VERSION 5.8 ;
BUSBITCHARS "[]" ;
DIVIDERCHAR "/" ;
UNITS
    DATABASE MICRONS 1000 ;
END UNITS

VIA ino_decode_queue_via1_2_1000_440_1_2_410_410
  VIARULE via1Array ;
  CUTSIZE 0.19 0.19 ;
  LAYERS Metal1 Via1 Metal2 ;
  CUTSPACING 0.22 0.22 ;
  ENCLOSURE 0.05 0.125 0.005 0.05 ;
  ROWCOL 1 2 ;
END ino_decode_queue_via1_2_1000_440_1_2_410_410

VIA ino_decode_queue_via2_3_1000_440_1_2_410_410
  VIARULE via2Array ;
  CUTSIZE 0.19 0.19 ;
  LAYERS Metal2 Via2 Metal3 ;
  CUTSPACING 0.22 0.22 ;
  ENCLOSURE 0.005 0.05 0.05 0.005 ;
  ROWCOL 1 2 ;
END ino_decode_queue_via2_3_1000_440_1_2_410_410

VIA ino_decode_queue_via3_4_1000_440_1_2_410_410
  VIARULE via3Array ;
  CUTSIZE 0.19 0.19 ;
  LAYERS Metal3 Via3 Metal4 ;
  CUTSPACING 0.22 0.22 ;
  ENCLOSURE 0.05 0.005 0.2 0.05 ;
  ROWCOL 1 2 ;
END ino_decode_queue_via3_4_1000_440_1_2_410_410

VIA ino_decode_queue_via4_5_1000_2000_1_1_840_840
  VIARULE viaTop1Array ;
  CUTSIZE 0.42 0.42 ;
  LAYERS Metal4 TopVia1 TopMetal1 ;
  CUTSPACING 0.42 0.42 ;
  ENCLOSURE 0.29 0.1 0.42 0.79 ;
END ino_decode_queue_via4_5_1000_2000_1_1_840_840

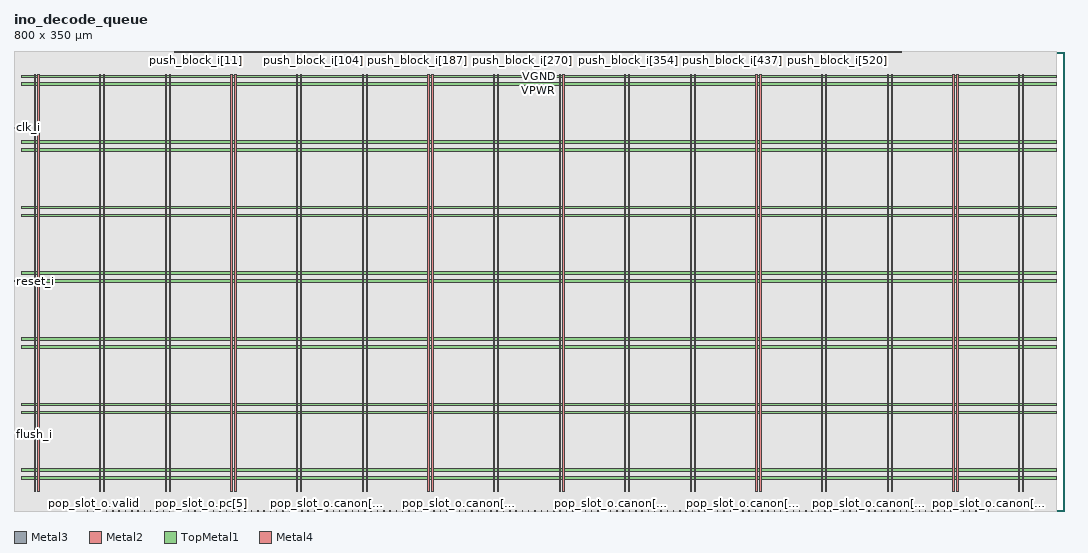
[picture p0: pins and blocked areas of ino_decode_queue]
MACRO ino_decode_queue
  FOREIGN ino_decode_queue 0 0 ;
  CLASS BLOCK ;
  SIZE 800 BY 350 ;
  PIN clk_i
    DIRECTION INPUT ;
    USE SIGNAL ;
    PORT
      LAYER Metal3 ;
        RECT  0 291.7 0.4 292.1 ;
    END
  END clk_i
  PIN flush_i
    DIRECTION INPUT ;
    USE SIGNAL ;
    PORT
      LAYER Metal3 ;
        RECT  0 58.18 0.4 58.58 ;
    END
  END flush_i
  PIN pop_slot_o.canon[0]
    DIRECTION OUTPUT ;
    USE SIGNAL ;
    PORT
      LAYER Metal2 ;
        RECT  65.56 0 65.96 0.4 ;
    END
  END pop_slot_o.canon[0]
  PIN pop_slot_o.canon[10]
    DIRECTION OUTPUT ;
    USE SIGNAL ;
    PORT
      LAYER Metal2 ;
        RECT  209.56 0 209.96 0.4 ;
    END
  END pop_slot_o.canon[10]
  PIN pop_slot_o.canon[11]
    DIRECTION OUTPUT ;
    USE SIGNAL ;
    PORT
      LAYER Metal2 ;
        RECT  223.96 0 224.36 0.4 ;
    END
  END pop_slot_o.canon[11]
  PIN pop_slot_o.canon[12]
    DIRECTION OUTPUT ;
    USE SIGNAL ;
    PORT
      LAYER Metal2 ;
        RECT  238.36 0 238.76 0.4 ;
    END
  END pop_slot_o.canon[12]
  PIN pop_slot_o.canon[13]
    DIRECTION OUTPUT ;
    USE SIGNAL ;
    PORT
      LAYER Metal2 ;
        RECT  252.76 0 253.16 0.4 ;
    END
  END pop_slot_o.canon[13]
  PIN pop_slot_o.canon[14]
    DIRECTION OUTPUT ;
    USE SIGNAL ;
    PORT
      LAYER Metal2 ;
        RECT  267.16 0 267.56 0.4 ;
    END
  END pop_slot_o.canon[14]
  PIN pop_slot_o.canon[15]
    DIRECTION OUTPUT ;
    USE SIGNAL ;
    PORT
      LAYER Metal2 ;
        RECT  281.56 0 281.96 0.4 ;
    END
  END pop_slot_o.canon[15]
  PIN pop_slot_o.canon[16]
    DIRECTION OUTPUT ;
    USE SIGNAL ;
    PORT
      LAYER Metal2 ;
        RECT  295.96 0 296.36 0.4 ;
    END
  END pop_slot_o.canon[16]
  PIN pop_slot_o.canon[17]
    DIRECTION OUTPUT ;
    USE SIGNAL ;
    PORT
      LAYER Metal2 ;
        RECT  310.36 0 310.76 0.4 ;
    END
  END pop_slot_o.canon[17]
  PIN pop_slot_o.canon[18]
    DIRECTION OUTPUT ;
    USE SIGNAL ;
    PORT
      LAYER Metal2 ;
        RECT  324.76 0 325.16 0.4 ;
    END
  END pop_slot_o.canon[18]
  PIN pop_slot_o.canon[19]
    DIRECTION OUTPUT ;
    USE SIGNAL ;
    PORT
      LAYER Metal2 ;
        RECT  339.16 0 339.56 0.4 ;
    END
  END pop_slot_o.canon[19]
  PIN pop_slot_o.canon[1]
    DIRECTION OUTPUT ;
    USE SIGNAL ;
    PORT
      LAYER Metal2 ;
        RECT  79.96 0 80.36 0.4 ;
    END
  END pop_slot_o.canon[1]
  PIN pop_slot_o.canon[20]
    DIRECTION OUTPUT ;
    USE SIGNAL ;
    PORT
      LAYER Metal2 ;
        RECT  353.56 0 353.96 0.4 ;
    END
  END pop_slot_o.canon[20]
  PIN pop_slot_o.canon[21]
    DIRECTION OUTPUT ;
    USE SIGNAL ;
    PORT
      LAYER Metal2 ;
        RECT  367.96 0 368.36 0.4 ;
    END
  END pop_slot_o.canon[21]
  PIN pop_slot_o.canon[22]
    DIRECTION OUTPUT ;
    USE SIGNAL ;
    PORT
      LAYER Metal2 ;
        RECT  382.36 0 382.76 0.4 ;
    END
  END pop_slot_o.canon[22]
  PIN pop_slot_o.canon[23]
    DIRECTION OUTPUT ;
    USE SIGNAL ;
    PORT
      LAYER Metal2 ;
        RECT  396.76 0 397.16 0.4 ;
    END
  END pop_slot_o.canon[23]
  PIN pop_slot_o.canon[24]
    DIRECTION OUTPUT ;
    USE SIGNAL ;
    PORT
      LAYER Metal2 ;
        RECT  411.16 0 411.56 0.4 ;
    END
  END pop_slot_o.canon[24]
  PIN pop_slot_o.canon[25]
    DIRECTION OUTPUT ;
    USE SIGNAL ;
    PORT
      LAYER Metal2 ;
        RECT  425.56 0 425.96 0.4 ;
    END
  END pop_slot_o.canon[25]
  PIN pop_slot_o.canon[26]
    DIRECTION OUTPUT ;
    USE SIGNAL ;
    PORT
      LAYER Metal2 ;
        RECT  439.96 0 440.36 0.4 ;
    END
  END pop_slot_o.canon[26]
  PIN pop_slot_o.canon[27]
    DIRECTION OUTPUT ;
    USE SIGNAL ;
    PORT
      LAYER Metal2 ;
        RECT  454.36 0 454.76 0.4 ;
    END
  END pop_slot_o.canon[27]
  PIN pop_slot_o.canon[28]
    DIRECTION OUTPUT ;
    USE SIGNAL ;
    PORT
      LAYER Metal2 ;
        RECT  468.76 0 469.16 0.4 ;
    END
  END pop_slot_o.canon[28]
  PIN pop_slot_o.canon[29]
    DIRECTION OUTPUT ;
    USE SIGNAL ;
    PORT
      LAYER Metal2 ;
        RECT  483.16 0 483.56 0.4 ;
    END
  END pop_slot_o.canon[29]
  PIN pop_slot_o.canon[2]
    DIRECTION OUTPUT ;
    USE SIGNAL ;
    PORT
      LAYER Metal2 ;
        RECT  94.36 0 94.76 0.4 ;
    END
  END pop_slot_o.canon[2]
  PIN pop_slot_o.canon[30]
    DIRECTION OUTPUT ;
    USE SIGNAL ;
    PORT
      LAYER Metal2 ;
        RECT  497.56 0 497.96 0.4 ;
    END
  END pop_slot_o.canon[30]
  PIN pop_slot_o.canon[31]
    DIRECTION OUTPUT ;
    USE SIGNAL ;
    PORT
      LAYER Metal2 ;
        RECT  511.96 0 512.36 0.4 ;
    END
  END pop_slot_o.canon[31]
  PIN pop_slot_o.canon[32]
    DIRECTION OUTPUT ;
    USE SIGNAL ;
    PORT
      LAYER Metal2 ;
        RECT  526.36 0 526.76 0.4 ;
    END
  END pop_slot_o.canon[32]
  PIN pop_slot_o.canon[33]
    DIRECTION OUTPUT ;
    USE SIGNAL ;
    PORT
      LAYER Metal2 ;
        RECT  535.96 0 536.36 0.4 ;
    END
  END pop_slot_o.canon[33]
  PIN pop_slot_o.canon[34]
    DIRECTION OUTPUT ;
    USE SIGNAL ;
    PORT
      LAYER Metal2 ;
        RECT  545.56 0 545.96 0.4 ;
    END
  END pop_slot_o.canon[34]
  PIN pop_slot_o.canon[35]
    DIRECTION OUTPUT ;
    USE SIGNAL ;
    PORT
      LAYER Metal2 ;
        RECT  555.16 0 555.56 0.4 ;
    END
  END pop_slot_o.canon[35]
  PIN pop_slot_o.canon[36]
    DIRECTION OUTPUT ;
    USE SIGNAL ;
    PORT
      LAYER Metal2 ;
        RECT  564.76 0 565.16 0.4 ;
    END
  END pop_slot_o.canon[36]
  PIN pop_slot_o.canon[37]
    DIRECTION OUTPUT ;
    USE SIGNAL ;
    PORT
      LAYER Metal2 ;
        RECT  574.36 0 574.76 0.4 ;
    END
  END pop_slot_o.canon[37]
  PIN pop_slot_o.canon[38]
    DIRECTION OUTPUT ;
    USE SIGNAL ;
    PORT
      LAYER Metal2 ;
        RECT  583.96 0 584.36 0.4 ;
    END
  END pop_slot_o.canon[38]
  PIN pop_slot_o.canon[39]
    DIRECTION OUTPUT ;
    USE SIGNAL ;
    PORT
      LAYER Metal2 ;
        RECT  593.56 0 593.96 0.4 ;
    END
  END pop_slot_o.canon[39]
  PIN pop_slot_o.canon[3]
    DIRECTION OUTPUT ;
    USE SIGNAL ;
    PORT
      LAYER Metal2 ;
        RECT  108.76 0 109.16 0.4 ;
    END
  END pop_slot_o.canon[3]
  PIN pop_slot_o.canon[40]
    DIRECTION OUTPUT ;
    USE SIGNAL ;
    PORT
      LAYER Metal2 ;
        RECT  603.16 0 603.56 0.4 ;
    END
  END pop_slot_o.canon[40]
  PIN pop_slot_o.canon[41]
    DIRECTION OUTPUT ;
    USE SIGNAL ;
    PORT
      LAYER Metal2 ;
        RECT  612.76 0 613.16 0.4 ;
    END
  END pop_slot_o.canon[41]
  PIN pop_slot_o.canon[42]
    DIRECTION OUTPUT ;
    USE SIGNAL ;
    PORT
      LAYER Metal2 ;
        RECT  622.36 0 622.76 0.4 ;
    END
  END pop_slot_o.canon[42]
  PIN pop_slot_o.canon[43]
    DIRECTION OUTPUT ;
    USE SIGNAL ;
    PORT
      LAYER Metal2 ;
        RECT  631.96 0 632.36 0.4 ;
    END
  END pop_slot_o.canon[43]
  PIN pop_slot_o.canon[44]
    DIRECTION OUTPUT ;
    USE SIGNAL ;
    PORT
      LAYER Metal2 ;
        RECT  641.56 0 641.96 0.4 ;
    END
  END pop_slot_o.canon[44]
  PIN pop_slot_o.canon[45]
    DIRECTION OUTPUT ;
    USE SIGNAL ;
    PORT
      LAYER Metal2 ;
        RECT  651.16 0 651.56 0.4 ;
    END
  END pop_slot_o.canon[45]
  PIN pop_slot_o.canon[46]
    DIRECTION OUTPUT ;
    USE SIGNAL ;
    PORT
      LAYER Metal2 ;
        RECT  660.76 0 661.16 0.4 ;
    END
  END pop_slot_o.canon[46]
  PIN pop_slot_o.canon[47]
    DIRECTION OUTPUT ;
    USE SIGNAL ;
    PORT
      LAYER Metal2 ;
        RECT  670.36 0 670.76 0.4 ;
    END
  END pop_slot_o.canon[47]
  PIN pop_slot_o.canon[48]
    DIRECTION OUTPUT ;
    USE SIGNAL ;
    PORT
      LAYER Metal2 ;
        RECT  679.96 0 680.36 0.4 ;
    END
  END pop_slot_o.canon[48]
  PIN pop_slot_o.canon[49]
    DIRECTION OUTPUT ;
    USE SIGNAL ;
    PORT
      LAYER Metal2 ;
        RECT  689.56 0 689.96 0.4 ;
    END
  END pop_slot_o.canon[49]
  PIN pop_slot_o.canon[4]
    DIRECTION OUTPUT ;
    USE SIGNAL ;
    PORT
      LAYER Metal2 ;
        RECT  123.16 0 123.56 0.4 ;
    END
  END pop_slot_o.canon[4]
  PIN pop_slot_o.canon[50]
    DIRECTION OUTPUT ;
    USE SIGNAL ;
    PORT
      LAYER Metal2 ;
        RECT  699.16 0 699.56 0.4 ;
    END
  END pop_slot_o.canon[50]
  PIN pop_slot_o.canon[51]
    DIRECTION OUTPUT ;
    USE SIGNAL ;
    PORT
      LAYER Metal2 ;
        RECT  708.76 0 709.16 0.4 ;
    END
  END pop_slot_o.canon[51]
  PIN pop_slot_o.canon[52]
    DIRECTION OUTPUT ;
    USE SIGNAL ;
    PORT
      LAYER Metal2 ;
        RECT  718.36 0 718.76 0.4 ;
    END
  END pop_slot_o.canon[52]
  PIN pop_slot_o.canon[53]
    DIRECTION OUTPUT ;
    USE SIGNAL ;
    PORT
      LAYER Metal2 ;
        RECT  727.96 0 728.36 0.4 ;
    END
  END pop_slot_o.canon[53]
  PIN pop_slot_o.canon[54]
    DIRECTION OUTPUT ;
    USE SIGNAL ;
    PORT
      LAYER Metal2 ;
        RECT  737.56 0 737.96 0.4 ;
    END
  END pop_slot_o.canon[54]
  PIN pop_slot_o.canon[55]
    DIRECTION OUTPUT ;
    USE SIGNAL ;
    PORT
      LAYER Metal2 ;
        RECT  742.36 0 742.76 0.4 ;
    END
  END pop_slot_o.canon[55]
  PIN pop_slot_o.canon[5]
    DIRECTION OUTPUT ;
    USE SIGNAL ;
    PORT
      LAYER Metal2 ;
        RECT  137.56 0 137.96 0.4 ;
    END
  END pop_slot_o.canon[5]
  PIN pop_slot_o.canon[6]
    DIRECTION OUTPUT ;
    USE SIGNAL ;
    PORT
      LAYER Metal2 ;
        RECT  151.96 0 152.36 0.4 ;
    END
  END pop_slot_o.canon[6]
  PIN pop_slot_o.canon[7]
    DIRECTION OUTPUT ;
    USE SIGNAL ;
    PORT
      LAYER Metal2 ;
        RECT  166.36 0 166.76 0.4 ;
    END
  END pop_slot_o.canon[7]
  PIN pop_slot_o.canon[8]
    DIRECTION OUTPUT ;
    USE SIGNAL ;
    PORT
      LAYER Metal2 ;
        RECT  180.76 0 181.16 0.4 ;
    END
  END pop_slot_o.canon[8]
  PIN pop_slot_o.canon[9]
    DIRECTION OUTPUT ;
    USE SIGNAL ;
    PORT
      LAYER Metal2 ;
        RECT  195.16 0 195.56 0.4 ;
    END
  END pop_slot_o.canon[9]
  PIN pop_slot_o.pc[0]
    DIRECTION OUTPUT ;
    USE SIGNAL ;
    PORT
      LAYER Metal2 ;
        RECT  70.36 0 70.76 0.4 ;
    END
  END pop_slot_o.pc[0]
  PIN pop_slot_o.pc[10]
    DIRECTION OUTPUT ;
    USE SIGNAL ;
    PORT
      LAYER Metal2 ;
        RECT  214.36 0 214.76 0.4 ;
    END
  END pop_slot_o.pc[10]
  PIN pop_slot_o.pc[11]
    DIRECTION OUTPUT ;
    USE SIGNAL ;
    PORT
      LAYER Metal2 ;
        RECT  228.76 0 229.16 0.4 ;
    END
  END pop_slot_o.pc[11]
  PIN pop_slot_o.pc[12]
    DIRECTION OUTPUT ;
    USE SIGNAL ;
    PORT
      LAYER Metal2 ;
        RECT  243.16 0 243.56 0.4 ;
    END
  END pop_slot_o.pc[12]
  PIN pop_slot_o.pc[13]
    DIRECTION OUTPUT ;
    USE SIGNAL ;
    PORT
      LAYER Metal2 ;
        RECT  257.56 0 257.96 0.4 ;
    END
  END pop_slot_o.pc[13]
  PIN pop_slot_o.pc[14]
    DIRECTION OUTPUT ;
    USE SIGNAL ;
    PORT
      LAYER Metal2 ;
        RECT  271.96 0 272.36 0.4 ;
    END
  END pop_slot_o.pc[14]
  PIN pop_slot_o.pc[15]
    DIRECTION OUTPUT ;
    USE SIGNAL ;
    PORT
      LAYER Metal2 ;
        RECT  286.36 0 286.76 0.4 ;
    END
  END pop_slot_o.pc[15]
  PIN pop_slot_o.pc[16]
    DIRECTION OUTPUT ;
    USE SIGNAL ;
    PORT
      LAYER Metal2 ;
        RECT  300.76 0 301.16 0.4 ;
    END
  END pop_slot_o.pc[16]
  PIN pop_slot_o.pc[17]
    DIRECTION OUTPUT ;
    USE SIGNAL ;
    PORT
      LAYER Metal2 ;
        RECT  315.16 0 315.56 0.4 ;
    END
  END pop_slot_o.pc[17]
  PIN pop_slot_o.pc[18]
    DIRECTION OUTPUT ;
    USE SIGNAL ;
    PORT
      LAYER Metal2 ;
        RECT  329.56 0 329.96 0.4 ;
    END
  END pop_slot_o.pc[18]
  PIN pop_slot_o.pc[19]
    DIRECTION OUTPUT ;
    USE SIGNAL ;
    PORT
      LAYER Metal2 ;
        RECT  343.96 0 344.36 0.4 ;
    END
  END pop_slot_o.pc[19]
  PIN pop_slot_o.pc[1]
    DIRECTION OUTPUT ;
    USE SIGNAL ;
    PORT
      LAYER Metal2 ;
        RECT  84.76 0 85.16 0.4 ;
    END
  END pop_slot_o.pc[1]
  PIN pop_slot_o.pc[20]
    DIRECTION OUTPUT ;
    USE SIGNAL ;
    PORT
      LAYER Metal2 ;
        RECT  358.36 0 358.76 0.4 ;
    END
  END pop_slot_o.pc[20]
  PIN pop_slot_o.pc[21]
    DIRECTION OUTPUT ;
    USE SIGNAL ;
    PORT
      LAYER Metal2 ;
        RECT  372.76 0 373.16 0.4 ;
    END
  END pop_slot_o.pc[21]
  PIN pop_slot_o.pc[22]
    DIRECTION OUTPUT ;
    USE SIGNAL ;
    PORT
      LAYER Metal2 ;
        RECT  387.16 0 387.56 0.4 ;
    END
  END pop_slot_o.pc[22]
  PIN pop_slot_o.pc[23]
    DIRECTION OUTPUT ;
    USE SIGNAL ;
    PORT
      LAYER Metal2 ;
        RECT  401.56 0 401.96 0.4 ;
    END
  END pop_slot_o.pc[23]
  PIN pop_slot_o.pc[24]
    DIRECTION OUTPUT ;
    USE SIGNAL ;
    PORT
      LAYER Metal2 ;
        RECT  415.96 0 416.36 0.4 ;
    END
  END pop_slot_o.pc[24]
  PIN pop_slot_o.pc[25]
    DIRECTION OUTPUT ;
    USE SIGNAL ;
    PORT
      LAYER Metal2 ;
        RECT  430.36 0 430.76 0.4 ;
    END
  END pop_slot_o.pc[25]
  PIN pop_slot_o.pc[26]
    DIRECTION OUTPUT ;
    USE SIGNAL ;
    PORT
      LAYER Metal2 ;
        RECT  444.76 0 445.16 0.4 ;
    END
  END pop_slot_o.pc[26]
  PIN pop_slot_o.pc[27]
    DIRECTION OUTPUT ;
    USE SIGNAL ;
    PORT
      LAYER Metal2 ;
        RECT  459.16 0 459.56 0.4 ;
    END
  END pop_slot_o.pc[27]
  PIN pop_slot_o.pc[28]
    DIRECTION OUTPUT ;
    USE SIGNAL ;
    PORT
      LAYER Metal2 ;
        RECT  473.56 0 473.96 0.4 ;
    END
  END pop_slot_o.pc[28]
  PIN pop_slot_o.pc[29]
    DIRECTION OUTPUT ;
    USE SIGNAL ;
    PORT
      LAYER Metal2 ;
        RECT  487.96 0 488.36 0.4 ;
    END
  END pop_slot_o.pc[29]
  PIN pop_slot_o.pc[2]
    DIRECTION OUTPUT ;
    USE SIGNAL ;
    PORT
      LAYER Metal2 ;
        RECT  99.16 0 99.56 0.4 ;
    END
  END pop_slot_o.pc[2]
  PIN pop_slot_o.pc[30]
    DIRECTION OUTPUT ;
    USE SIGNAL ;
    PORT
      LAYER Metal2 ;
        RECT  502.36 0 502.76 0.4 ;
    END
  END pop_slot_o.pc[30]
  PIN pop_slot_o.pc[31]
    DIRECTION OUTPUT ;
    USE SIGNAL ;
    PORT
      LAYER Metal2 ;
        RECT  516.76 0 517.16 0.4 ;
    END
  END pop_slot_o.pc[31]
  PIN pop_slot_o.pc[3]
    DIRECTION OUTPUT ;
    USE SIGNAL ;
    PORT
      LAYER Metal2 ;
        RECT  113.56 0 113.96 0.4 ;
    END
  END pop_slot_o.pc[3]
  PIN pop_slot_o.pc[4]
    DIRECTION OUTPUT ;
    USE SIGNAL ;
    PORT
      LAYER Metal2 ;
        RECT  127.96 0 128.36 0.4 ;
    END
  END pop_slot_o.pc[4]
  PIN pop_slot_o.pc[5]
    DIRECTION OUTPUT ;
    USE SIGNAL ;
    PORT
      LAYER Metal2 ;
        RECT  142.36 0 142.76 0.4 ;
    END
  END pop_slot_o.pc[5]
  PIN pop_slot_o.pc[6]
    DIRECTION OUTPUT ;
    USE SIGNAL ;
    PORT
      LAYER Metal2 ;
        RECT  156.76 0 157.16 0.4 ;
    END
  END pop_slot_o.pc[6]
  PIN pop_slot_o.pc[7]
    DIRECTION OUTPUT ;
    USE SIGNAL ;
    PORT
      LAYER Metal2 ;
        RECT  171.16 0 171.56 0.4 ;
    END
  END pop_slot_o.pc[7]
  PIN pop_slot_o.pc[8]
    DIRECTION OUTPUT ;
    USE SIGNAL ;
    PORT
      LAYER Metal2 ;
        RECT  185.56 0 185.96 0.4 ;
    END
  END pop_slot_o.pc[8]
  PIN pop_slot_o.pc[9]
    DIRECTION OUTPUT ;
    USE SIGNAL ;
    PORT
      LAYER Metal2 ;
        RECT  199.96 0 200.36 0.4 ;
    END
  END pop_slot_o.pc[9]
  PIN pop_slot_o.pred[0]
    DIRECTION OUTPUT ;
    USE SIGNAL ;
    PORT
      LAYER Metal2 ;
        RECT  75.16 0 75.56 0.4 ;
    END
  END pop_slot_o.pred[0]
  PIN pop_slot_o.pred[10]
    DIRECTION OUTPUT ;
    USE SIGNAL ;
    PORT
      LAYER Metal2 ;
        RECT  219.16 0 219.56 0.4 ;
    END
  END pop_slot_o.pred[10]
  PIN pop_slot_o.pred[11]
    DIRECTION OUTPUT ;
    USE SIGNAL ;
    PORT
      LAYER Metal2 ;
        RECT  233.56 0 233.96 0.4 ;
    END
  END pop_slot_o.pred[11]
  PIN pop_slot_o.pred[12]
    DIRECTION OUTPUT ;
    USE SIGNAL ;
    PORT
      LAYER Metal2 ;
        RECT  247.96 0 248.36 0.4 ;
    END
  END pop_slot_o.pred[12]
  PIN pop_slot_o.pred[13]
    DIRECTION OUTPUT ;
    USE SIGNAL ;
    PORT
      LAYER Metal2 ;
        RECT  262.36 0 262.76 0.4 ;
    END
  END pop_slot_o.pred[13]
  PIN pop_slot_o.pred[14]
    DIRECTION OUTPUT ;
    USE SIGNAL ;
    PORT
      LAYER Metal2 ;
        RECT  276.76 0 277.16 0.4 ;
    END
  END pop_slot_o.pred[14]
  PIN pop_slot_o.pred[15]
    DIRECTION OUTPUT ;
    USE SIGNAL ;
    PORT
      LAYER Metal2 ;
        RECT  291.16 0 291.56 0.4 ;
    END
  END pop_slot_o.pred[15]
  PIN pop_slot_o.pred[16]
    DIRECTION OUTPUT ;
    USE SIGNAL ;
    PORT
      LAYER Metal2 ;
        RECT  305.56 0 305.96 0.4 ;
    END
  END pop_slot_o.pred[16]
  PIN pop_slot_o.pred[17]
    DIRECTION OUTPUT ;
    USE SIGNAL ;
    PORT
      LAYER Metal2 ;
        RECT  319.96 0 320.36 0.4 ;
    END
  END pop_slot_o.pred[17]
  PIN pop_slot_o.pred[18]
    DIRECTION OUTPUT ;
    USE SIGNAL ;
    PORT
      LAYER Metal2 ;
        RECT  334.36 0 334.76 0.4 ;
    END
  END pop_slot_o.pred[18]
  PIN pop_slot_o.pred[19]
    DIRECTION OUTPUT ;
    USE SIGNAL ;
    PORT
      LAYER Metal2 ;
        RECT  348.76 0 349.16 0.4 ;
    END
  END pop_slot_o.pred[19]
  PIN pop_slot_o.pred[1]
    DIRECTION OUTPUT ;
    USE SIGNAL ;
    PORT
      LAYER Metal2 ;
        RECT  89.56 0 89.96 0.4 ;
    END
  END pop_slot_o.pred[1]
  PIN pop_slot_o.pred[20]
    DIRECTION OUTPUT ;
    USE SIGNAL ;
    PORT
      LAYER Metal2 ;
        RECT  363.16 0 363.56 0.4 ;
    END
  END pop_slot_o.pred[20]
  PIN pop_slot_o.pred[21]
    DIRECTION OUTPUT ;
    USE SIGNAL ;
    PORT
      LAYER Metal2 ;
        RECT  377.56 0 377.96 0.4 ;
    END
  END pop_slot_o.pred[21]
  PIN pop_slot_o.pred[22]
    DIRECTION OUTPUT ;
    USE SIGNAL ;
    PORT
      LAYER Metal2 ;
        RECT  391.96 0 392.36 0.4 ;
    END
  END pop_slot_o.pred[22]
  PIN pop_slot_o.pred[23]
    DIRECTION OUTPUT ;
    USE SIGNAL ;
    PORT
      LAYER Metal2 ;
        RECT  406.36 0 406.76 0.4 ;
    END
  END pop_slot_o.pred[23]
  PIN pop_slot_o.pred[24]
    DIRECTION OUTPUT ;
    USE SIGNAL ;
    PORT
      LAYER Metal2 ;
        RECT  420.76 0 421.16 0.4 ;
    END
  END pop_slot_o.pred[24]
  PIN pop_slot_o.pred[25]
    DIRECTION OUTPUT ;
    USE SIGNAL ;
    PORT
      LAYER Metal2 ;
        RECT  435.16 0 435.56 0.4 ;
    END
  END pop_slot_o.pred[25]
  PIN pop_slot_o.pred[26]
    DIRECTION OUTPUT ;
    USE SIGNAL ;
    PORT
      LAYER Metal2 ;
        RECT  449.56 0 449.96 0.4 ;
    END
  END pop_slot_o.pred[26]
  PIN pop_slot_o.pred[27]
    DIRECTION OUTPUT ;
    USE SIGNAL ;
    PORT
      LAYER Metal2 ;
        RECT  463.96 0 464.36 0.4 ;
    END
  END pop_slot_o.pred[27]
  PIN pop_slot_o.pred[28]
    DIRECTION OUTPUT ;
    USE SIGNAL ;
    PORT
      LAYER Metal2 ;
        RECT  478.36 0 478.76 0.4 ;
    END
  END pop_slot_o.pred[28]
  PIN pop_slot_o.pred[29]
    DIRECTION OUTPUT ;
    USE SIGNAL ;
    PORT
      LAYER Metal2 ;
        RECT  492.76 0 493.16 0.4 ;
    END
  END pop_slot_o.pred[29]
  PIN pop_slot_o.pred[2]
    DIRECTION OUTPUT ;
    USE SIGNAL ;
    PORT
      LAYER Metal2 ;
        RECT  103.96 0 104.36 0.4 ;
    END
  END pop_slot_o.pred[2]
  PIN pop_slot_o.pred[30]
    DIRECTION OUTPUT ;
    USE SIGNAL ;
    PORT
      LAYER Metal2 ;
        RECT  507.16 0 507.56 0.4 ;
    END
  END pop_slot_o.pred[30]
  PIN pop_slot_o.pred[31]
    DIRECTION OUTPUT ;
    USE SIGNAL ;
    PORT
      LAYER Metal2 ;
        RECT  521.56 0 521.96 0.4 ;
    END
  END pop_slot_o.pred[31]
  PIN pop_slot_o.pred[32]
    DIRECTION OUTPUT ;
    USE SIGNAL ;
    PORT
      LAYER Metal2 ;
        RECT  531.16 0 531.56 0.4 ;
    END
  END pop_slot_o.pred[32]
  PIN pop_slot_o.pred[33]
    DIRECTION OUTPUT ;
    USE SIGNAL ;
    PORT
      LAYER Metal2 ;
        RECT  540.76 0 541.16 0.4 ;
    END
  END pop_slot_o.pred[33]
  PIN pop_slot_o.pred[34]
    DIRECTION OUTPUT ;
    USE SIGNAL ;
    PORT
      LAYER Metal2 ;
        RECT  550.36 0 550.76 0.4 ;
    END
  END pop_slot_o.pred[34]
  PIN pop_slot_o.pred[35]
    DIRECTION OUTPUT ;
    USE SIGNAL ;
    PORT
      LAYER Metal2 ;
        RECT  559.96 0 560.36 0.4 ;
    END
  END pop_slot_o.pred[35]
  PIN pop_slot_o.pred[36]
    DIRECTION OUTPUT ;
    USE SIGNAL ;
    PORT
      LAYER Metal2 ;
        RECT  569.56 0 569.96 0.4 ;
    END
  END pop_slot_o.pred[36]
  PIN pop_slot_o.pred[37]
    DIRECTION OUTPUT ;
    USE SIGNAL ;
    PORT
      LAYER Metal2 ;
        RECT  579.16 0 579.56 0.4 ;
    END
  END pop_slot_o.pred[37]
  PIN pop_slot_o.pred[38]
    DIRECTION OUTPUT ;
    USE SIGNAL ;
    PORT
      LAYER Metal2 ;
        RECT  588.76 0 589.16 0.4 ;
    END
  END pop_slot_o.pred[38]
  PIN pop_slot_o.pred[39]
    DIRECTION OUTPUT ;
    USE SIGNAL ;
    PORT
      LAYER Metal2 ;
        RECT  598.36 0 598.76 0.4 ;
    END
  END pop_slot_o.pred[39]
  PIN pop_slot_o.pred[3]
    DIRECTION OUTPUT ;
    USE SIGNAL ;
    PORT
      LAYER Metal2 ;
        RECT  118.36 0 118.76 0.4 ;
    END
  END pop_slot_o.pred[3]
  PIN pop_slot_o.pred[40]
    DIRECTION OUTPUT ;
    USE SIGNAL ;
    PORT
      LAYER Metal2 ;
        RECT  607.96 0 608.36 0.4 ;
    END
  END pop_slot_o.pred[40]
  PIN pop_slot_o.pred[41]
    DIRECTION OUTPUT ;
    USE SIGNAL ;
    PORT
      LAYER Metal2 ;
        RECT  617.56 0 617.96 0.4 ;
    END
  END pop_slot_o.pred[41]
  PIN pop_slot_o.pred[42]
    DIRECTION OUTPUT ;
    USE SIGNAL ;
    PORT
      LAYER Metal2 ;
        RECT  627.16 0 627.56 0.4 ;
    END
  END pop_slot_o.pred[42]
  PIN pop_slot_o.pred[43]
    DIRECTION OUTPUT ;
    USE SIGNAL ;
    PORT
      LAYER Metal2 ;
        RECT  636.76 0 637.16 0.4 ;
    END
  END pop_slot_o.pred[43]
  PIN pop_slot_o.pred[44]
    DIRECTION OUTPUT ;
    USE SIGNAL ;
    PORT
      LAYER Metal2 ;
        RECT  646.36 0 646.76 0.4 ;
    END
  END pop_slot_o.pred[44]
  PIN pop_slot_o.pred[45]
    DIRECTION OUTPUT ;
    USE SIGNAL ;
    PORT
      LAYER Metal2 ;
        RECT  655.96 0 656.36 0.4 ;
    END
  END pop_slot_o.pred[45]
  PIN pop_slot_o.pred[46]
    DIRECTION OUTPUT ;
    USE SIGNAL ;
    PORT
      LAYER Metal2 ;
        RECT  665.56 0 665.96 0.4 ;
    END
  END pop_slot_o.pred[46]
  PIN pop_slot_o.pred[47]
    DIRECTION OUTPUT ;
    USE SIGNAL ;
    PORT
      LAYER Metal2 ;
        RECT  675.16 0 675.56 0.4 ;
    END
  END pop_slot_o.pred[47]
  PIN pop_slot_o.pred[48]
    DIRECTION OUTPUT ;
    USE SIGNAL ;
    PORT
      LAYER Metal2 ;
        RECT  684.76 0 685.16 0.4 ;
    END
  END pop_slot_o.pred[48]
  PIN pop_slot_o.pred[49]
    DIRECTION OUTPUT ;
    USE SIGNAL ;
    PORT
      LAYER Metal2 ;
        RECT  694.36 0 694.76 0.4 ;
    END
  END pop_slot_o.pred[49]
  PIN pop_slot_o.pred[4]
    DIRECTION OUTPUT ;
    USE SIGNAL ;
    PORT
      LAYER Metal2 ;
        RECT  132.76 0 133.16 0.4 ;
    END
  END pop_slot_o.pred[4]
  PIN pop_slot_o.pred[50]
    DIRECTION OUTPUT ;
    USE SIGNAL ;
    PORT
      LAYER Metal2 ;
        RECT  703.96 0 704.36 0.4 ;
    END
  END pop_slot_o.pred[50]
  PIN pop_slot_o.pred[51]
    DIRECTION OUTPUT ;
    USE SIGNAL ;
    PORT
      LAYER Metal2 ;
        RECT  713.56 0 713.96 0.4 ;
    END
  END pop_slot_o.pred[51]
  PIN pop_slot_o.pred[52]
    DIRECTION OUTPUT ;
    USE SIGNAL ;
    PORT
      LAYER Metal2 ;
        RECT  723.16 0 723.56 0.4 ;
    END
  END pop_slot_o.pred[52]
  PIN pop_slot_o.pred[53]
    DIRECTION OUTPUT ;
    USE SIGNAL ;
    PORT
      LAYER Metal2 ;
        RECT  732.76 0 733.16 0.4 ;
    END
  END pop_slot_o.pred[53]
  PIN pop_slot_o.pred[5]
    DIRECTION OUTPUT ;
    USE SIGNAL ;
    PORT
      LAYER Metal2 ;
        RECT  147.16 0 147.56 0.4 ;
    END
  END pop_slot_o.pred[5]
  PIN pop_slot_o.pred[6]
    DIRECTION OUTPUT ;
    USE SIGNAL ;
    PORT
      LAYER Metal2 ;
        RECT  161.56 0 161.96 0.4 ;
    END
  END pop_slot_o.pred[6]
  PIN pop_slot_o.pred[7]
    DIRECTION OUTPUT ;
    USE SIGNAL ;
    PORT
      LAYER Metal2 ;
        RECT  175.96 0 176.36 0.4 ;
    END
  END pop_slot_o.pred[7]
  PIN pop_slot_o.pred[8]
    DIRECTION OUTPUT ;
    USE SIGNAL ;
    PORT
      LAYER Metal2 ;
        RECT  190.36 0 190.76 0.4 ;
    END
  END pop_slot_o.pred[8]
  PIN pop_slot_o.pred[9]
    DIRECTION OUTPUT ;
    USE SIGNAL ;
    PORT
      LAYER Metal2 ;
        RECT  204.76 0 205.16 0.4 ;
    END
  END pop_slot_o.pred[9]
  PIN pop_slot_o.valid
    DIRECTION OUTPUT ;
    USE SIGNAL ;
    PORT
      LAYER Metal2 ;
        RECT  60.76 0 61.16 0.4 ;
    END
  END pop_slot_o.valid
  PIN pop_take_i
    DIRECTION INPUT ;
    USE SIGNAL ;
    PORT
      LAYER Metal2 ;
        RECT  55.96 0 56.36 0.4 ;
    END
  END pop_take_i
  PIN push_block_i[0]
    DIRECTION INPUT ;
    USE SIGNAL ;
    PORT
      LAYER Metal2 ;
        RECT  127.96 349.6 128.36 350 ;
    END
  END push_block_i[0]
  PIN push_block_i[100]
    DIRECTION INPUT ;
    USE SIGNAL ;
    PORT
      LAYER Metal2 ;
        RECT  223.96 349.6 224.36 350 ;
    END
  END push_block_i[100]
  PIN push_block_i[101]
    DIRECTION INPUT ;
    USE SIGNAL ;
    PORT
      LAYER Metal2 ;
        RECT  224.92 349.6 225.32 350 ;
    END
  END push_block_i[101]
  PIN push_block_i[102]
    DIRECTION INPUT ;
    USE SIGNAL ;
    PORT
      LAYER Metal2 ;
        RECT  225.88 349.6 226.28 350 ;
    END
  END push_block_i[102]
  PIN push_block_i[103]
    DIRECTION INPUT ;
    USE SIGNAL ;
    PORT
      LAYER Metal2 ;
        RECT  226.84 349.6 227.24 350 ;
    END
  END push_block_i[103]
  PIN push_block_i[104]
    DIRECTION INPUT ;
    USE SIGNAL ;
    PORT
      LAYER Metal2 ;
        RECT  227.8 349.6 228.2 350 ;
    END
  END push_block_i[104]
  PIN push_block_i[105]
    DIRECTION INPUT ;
    USE SIGNAL ;
    PORT
      LAYER Metal2 ;
        RECT  228.76 349.6 229.16 350 ;
    END
  END push_block_i[105]
  PIN push_block_i[106]
    DIRECTION INPUT ;
    USE SIGNAL ;
    PORT
      LAYER Metal2 ;
        RECT  229.72 349.6 230.12 350 ;
    END
  END push_block_i[106]
  PIN push_block_i[107]
    DIRECTION INPUT ;
    USE SIGNAL ;
    PORT
      LAYER Metal2 ;
        RECT  230.68 349.6 231.08 350 ;
    END
  END push_block_i[107]
  PIN push_block_i[108]
    DIRECTION INPUT ;
    USE SIGNAL ;
    PORT
      LAYER Metal2 ;
        RECT  231.64 349.6 232.04 350 ;
    END
  END push_block_i[108]
  PIN push_block_i[109]
    DIRECTION INPUT ;
    USE SIGNAL ;
    PORT
      LAYER Metal2 ;
        RECT  232.6 349.6 233 350 ;
    END
  END push_block_i[109]
  PIN push_block_i[10]
    DIRECTION INPUT ;
    USE SIGNAL ;
    PORT
      LAYER Metal2 ;
        RECT  137.56 349.6 137.96 350 ;
    END
  END push_block_i[10]
  PIN push_block_i[110]
    DIRECTION INPUT ;
    USE SIGNAL ;
    PORT
      LAYER Metal2 ;
        RECT  233.56 349.6 233.96 350 ;
    END
  END push_block_i[110]
  PIN push_block_i[111]
    DIRECTION INPUT ;
    USE SIGNAL ;
    PORT
      LAYER Metal2 ;
        RECT  234.52 349.6 234.92 350 ;
    END
  END push_block_i[111]
  PIN push_block_i[112]
    DIRECTION INPUT ;
    USE SIGNAL ;
    PORT
      LAYER Metal2 ;
        RECT  235.48 349.6 235.88 350 ;
    END
  END push_block_i[112]
  PIN push_block_i[113]
    DIRECTION INPUT ;
    USE SIGNAL ;
    PORT
      LAYER Metal2 ;
        RECT  236.44 349.6 236.84 350 ;
    END
  END push_block_i[113]
  PIN push_block_i[114]
    DIRECTION INPUT ;
    USE SIGNAL ;
    PORT
      LAYER Metal2 ;
        RECT  237.4 349.6 237.8 350 ;
    END
  END push_block_i[114]
  PIN push_block_i[115]
    DIRECTION INPUT ;
    USE SIGNAL ;
    PORT
      LAYER Metal2 ;
        RECT  238.36 349.6 238.76 350 ;
    END
  END push_block_i[115]
  PIN push_block_i[116]
    DIRECTION INPUT ;
    USE SIGNAL ;
    PORT
      LAYER Metal2 ;
        RECT  239.32 349.6 239.72 350 ;
    END
  END push_block_i[116]
  PIN push_block_i[117]
    DIRECTION INPUT ;
    USE SIGNAL ;
    PORT
      LAYER Metal2 ;
        RECT  240.28 349.6 240.68 350 ;
    END
  END push_block_i[117]
  PIN push_block_i[118]
    DIRECTION INPUT ;
    USE SIGNAL ;
    PORT
      LAYER Metal2 ;
        RECT  241.24 349.6 241.64 350 ;
    END
  END push_block_i[118]
  PIN push_block_i[119]
    DIRECTION INPUT ;
    USE SIGNAL ;
    PORT
      LAYER Metal2 ;
        RECT  242.2 349.6 242.6 350 ;
    END
  END push_block_i[119]
  PIN push_block_i[11]
    DIRECTION INPUT ;
    USE SIGNAL ;
    PORT
      LAYER Metal2 ;
        RECT  138.52 349.6 138.92 350 ;
    END
  END push_block_i[11]
  PIN push_block_i[120]
    DIRECTION INPUT ;
    USE SIGNAL ;
    PORT
      LAYER Metal2 ;
        RECT  243.16 349.6 243.56 350 ;
    END
  END push_block_i[120]
  PIN push_block_i[121]
    DIRECTION INPUT ;
    USE SIGNAL ;
    PORT
      LAYER Metal2 ;
        RECT  244.12 349.6 244.52 350 ;
    END
  END push_block_i[121]
  PIN push_block_i[122]
    DIRECTION INPUT ;
    USE SIGNAL ;
    PORT
      LAYER Metal2 ;
        RECT  245.08 349.6 245.48 350 ;
    END
  END push_block_i[122]
  PIN push_block_i[123]
    DIRECTION INPUT ;
    USE SIGNAL ;
    PORT
      LAYER Metal2 ;
        RECT  246.04 349.6 246.44 350 ;
    END
  END push_block_i[123]
  PIN push_block_i[124]
    DIRECTION INPUT ;
    USE SIGNAL ;
    PORT
      LAYER Metal2 ;
        RECT  247 349.6 247.4 350 ;
    END
  END push_block_i[124]
  PIN push_block_i[125]
    DIRECTION INPUT ;
    USE SIGNAL ;
    PORT
      LAYER Metal2 ;
        RECT  247.96 349.6 248.36 350 ;
    END
  END push_block_i[125]
  PIN push_block_i[126]
    DIRECTION INPUT ;
    USE SIGNAL ;
    PORT
      LAYER Metal2 ;
        RECT  248.92 349.6 249.32 350 ;
    END
  END push_block_i[126]
  PIN push_block_i[127]
    DIRECTION INPUT ;
    USE SIGNAL ;
    PORT
      LAYER Metal2 ;
        RECT  249.88 349.6 250.28 350 ;
    END
  END push_block_i[127]
  PIN push_block_i[128]
    DIRECTION INPUT ;
    USE SIGNAL ;
    PORT
      LAYER Metal2 ;
        RECT  250.84 349.6 251.24 350 ;
    END
  END push_block_i[128]
  PIN push_block_i[129]
    DIRECTION INPUT ;
    USE SIGNAL ;
    PORT
      LAYER Metal2 ;
        RECT  251.8 349.6 252.2 350 ;
    END
  END push_block_i[129]
  PIN push_block_i[12]
    DIRECTION INPUT ;
    USE SIGNAL ;
    PORT
      LAYER Metal2 ;
        RECT  139.48 349.6 139.88 350 ;
    END
  END push_block_i[12]
  PIN push_block_i[130]
    DIRECTION INPUT ;
    USE SIGNAL ;
    PORT
      LAYER Metal2 ;
        RECT  252.76 349.6 253.16 350 ;
    END
  END push_block_i[130]
  PIN push_block_i[131]
    DIRECTION INPUT ;
    USE SIGNAL ;
    PORT
      LAYER Metal2 ;
        RECT  253.72 349.6 254.12 350 ;
    END
  END push_block_i[131]
  PIN push_block_i[132]
    DIRECTION INPUT ;
    USE SIGNAL ;
    PORT
      LAYER Metal2 ;
        RECT  254.68 349.6 255.08 350 ;
    END
  END push_block_i[132]
  PIN push_block_i[133]
    DIRECTION INPUT ;
    USE SIGNAL ;
    PORT
      LAYER Metal2 ;
        RECT  255.64 349.6 256.04 350 ;
    END
  END push_block_i[133]
  PIN push_block_i[134]
    DIRECTION INPUT ;
    USE SIGNAL ;
    PORT
      LAYER Metal2 ;
        RECT  256.6 349.6 257 350 ;
    END
  END push_block_i[134]
  PIN push_block_i[135]
    DIRECTION INPUT ;
    USE SIGNAL ;
    PORT
      LAYER Metal2 ;
        RECT  257.56 349.6 257.96 350 ;
    END
  END push_block_i[135]
  PIN push_block_i[136]
    DIRECTION INPUT ;
    USE SIGNAL ;
    PORT
      LAYER Metal2 ;
        RECT  258.52 349.6 258.92 350 ;
    END
  END push_block_i[136]
  PIN push_block_i[137]
    DIRECTION INPUT ;
    USE SIGNAL ;
    PORT
      LAYER Metal2 ;
        RECT  259.48 349.6 259.88 350 ;
    END
  END push_block_i[137]
  PIN push_block_i[138]
    DIRECTION INPUT ;
    USE SIGNAL ;
    PORT
      LAYER Metal2 ;
        RECT  260.44 349.6 260.84 350 ;
    END
  END push_block_i[138]
  PIN push_block_i[139]
    DIRECTION INPUT ;
    USE SIGNAL ;
    PORT
      LAYER Metal2 ;
        RECT  261.4 349.6 261.8 350 ;
    END
  END push_block_i[139]
  PIN push_block_i[13]
    DIRECTION INPUT ;
    USE SIGNAL ;
    PORT
      LAYER Metal2 ;
        RECT  140.44 349.6 140.84 350 ;
    END
  END push_block_i[13]
  PIN push_block_i[140]
    DIRECTION INPUT ;
    USE SIGNAL ;
    PORT
      LAYER Metal2 ;
        RECT  262.36 349.6 262.76 350 ;
    END
  END push_block_i[140]
  PIN push_block_i[141]
    DIRECTION INPUT ;
    USE SIGNAL ;
    PORT
      LAYER Metal2 ;
        RECT  263.32 349.6 263.72 350 ;
    END
  END push_block_i[141]
  PIN push_block_i[142]
    DIRECTION INPUT ;
    USE SIGNAL ;
    PORT
      LAYER Metal2 ;
        RECT  264.28 349.6 264.68 350 ;
    END
  END push_block_i[142]
  PIN push_block_i[143]
    DIRECTION INPUT ;
    USE SIGNAL ;
    PORT
      LAYER Metal2 ;
        RECT  265.24 349.6 265.64 350 ;
    END
  END push_block_i[143]
  PIN push_block_i[144]
    DIRECTION INPUT ;
    USE SIGNAL ;
    PORT
      LAYER Metal2 ;
        RECT  266.2 349.6 266.6 350 ;
    END
  END push_block_i[144]
  PIN push_block_i[145]
    DIRECTION INPUT ;
    USE SIGNAL ;
    PORT
      LAYER Metal2 ;
        RECT  267.16 349.6 267.56 350 ;
    END
  END push_block_i[145]
  PIN push_block_i[146]
    DIRECTION INPUT ;
    USE SIGNAL ;
    PORT
      LAYER Metal2 ;
        RECT  268.12 349.6 268.52 350 ;
    END
  END push_block_i[146]
  PIN push_block_i[147]
    DIRECTION INPUT ;
    USE SIGNAL ;
    PORT
      LAYER Metal2 ;
        RECT  269.08 349.6 269.48 350 ;
    END
  END push_block_i[147]
  PIN push_block_i[148]
    DIRECTION INPUT ;
    USE SIGNAL ;
    PORT
      LAYER Metal2 ;
        RECT  270.04 349.6 270.44 350 ;
    END
  END push_block_i[148]
  PIN push_block_i[149]
    DIRECTION INPUT ;
    USE SIGNAL ;
    PORT
      LAYER Metal2 ;
        RECT  271 349.6 271.4 350 ;
    END
  END push_block_i[149]
  PIN push_block_i[14]
    DIRECTION INPUT ;
    USE SIGNAL ;
    PORT
      LAYER Metal2 ;
        RECT  141.4 349.6 141.8 350 ;
    END
  END push_block_i[14]
  PIN push_block_i[150]
    DIRECTION INPUT ;
    USE SIGNAL ;
    PORT
      LAYER Metal2 ;
        RECT  271.96 349.6 272.36 350 ;
    END
  END push_block_i[150]
  PIN push_block_i[151]
    DIRECTION INPUT ;
    USE SIGNAL ;
    PORT
      LAYER Metal2 ;
        RECT  272.92 349.6 273.32 350 ;
    END
  END push_block_i[151]
  PIN push_block_i[152]
    DIRECTION INPUT ;
    USE SIGNAL ;
    PORT
      LAYER Metal2 ;
        RECT  273.88 349.6 274.28 350 ;
    END
  END push_block_i[152]
  PIN push_block_i[153]
    DIRECTION INPUT ;
    USE SIGNAL ;
    PORT
      LAYER Metal2 ;
        RECT  274.84 349.6 275.24 350 ;
    END
  END push_block_i[153]
  PIN push_block_i[154]
    DIRECTION INPUT ;
    USE SIGNAL ;
    PORT
      LAYER Metal2 ;
        RECT  275.8 349.6 276.2 350 ;
    END
  END push_block_i[154]
  PIN push_block_i[155]
    DIRECTION INPUT ;
    USE SIGNAL ;
    PORT
      LAYER Metal2 ;
        RECT  276.76 349.6 277.16 350 ;
    END
  END push_block_i[155]
  PIN push_block_i[156]
    DIRECTION INPUT ;
    USE SIGNAL ;
    PORT
      LAYER Metal2 ;
        RECT  277.72 349.6 278.12 350 ;
    END
  END push_block_i[156]
  PIN push_block_i[157]
    DIRECTION INPUT ;
    USE SIGNAL ;
    PORT
      LAYER Metal2 ;
        RECT  278.68 349.6 279.08 350 ;
    END
  END push_block_i[157]
  PIN push_block_i[158]
    DIRECTION INPUT ;
    USE SIGNAL ;
    PORT
      LAYER Metal2 ;
        RECT  279.64 349.6 280.04 350 ;
    END
  END push_block_i[158]
  PIN push_block_i[159]
    DIRECTION INPUT ;
    USE SIGNAL ;
    PORT
      LAYER Metal2 ;
        RECT  280.6 349.6 281 350 ;
    END
  END push_block_i[159]
  PIN push_block_i[15]
    DIRECTION INPUT ;
    USE SIGNAL ;
    PORT
      LAYER Metal2 ;
        RECT  142.36 349.6 142.76 350 ;
    END
  END push_block_i[15]
  PIN push_block_i[160]
    DIRECTION INPUT ;
    USE SIGNAL ;
    PORT
      LAYER Metal2 ;
        RECT  281.56 349.6 281.96 350 ;
    END
  END push_block_i[160]
  PIN push_block_i[161]
    DIRECTION INPUT ;
    USE SIGNAL ;
    PORT
      LAYER Metal2 ;
        RECT  282.52 349.6 282.92 350 ;
    END
  END push_block_i[161]
  PIN push_block_i[162]
    DIRECTION INPUT ;
    USE SIGNAL ;
    PORT
      LAYER Metal2 ;
        RECT  283.48 349.6 283.88 350 ;
    END
  END push_block_i[162]
  PIN push_block_i[163]
    DIRECTION INPUT ;
    USE SIGNAL ;
    PORT
      LAYER Metal2 ;
        RECT  284.44 349.6 284.84 350 ;
    END
  END push_block_i[163]
  PIN push_block_i[164]
    DIRECTION INPUT ;
    USE SIGNAL ;
    PORT
      LAYER Metal2 ;
        RECT  285.4 349.6 285.8 350 ;
    END
  END push_block_i[164]
  PIN push_block_i[165]
    DIRECTION INPUT ;
    USE SIGNAL ;
    PORT
      LAYER Metal2 ;
        RECT  286.36 349.6 286.76 350 ;
    END
  END push_block_i[165]
  PIN push_block_i[166]
    DIRECTION INPUT ;
    USE SIGNAL ;
    PORT
      LAYER Metal2 ;
        RECT  287.32 349.6 287.72 350 ;
    END
  END push_block_i[166]
  PIN push_block_i[167]
    DIRECTION INPUT ;
    USE SIGNAL ;
    PORT
      LAYER Metal2 ;
        RECT  288.28 349.6 288.68 350 ;
    END
  END push_block_i[167]
  PIN push_block_i[168]
    DIRECTION INPUT ;
    USE SIGNAL ;
    PORT
      LAYER Metal2 ;
        RECT  289.24 349.6 289.64 350 ;
    END
  END push_block_i[168]
  PIN push_block_i[169]
    DIRECTION INPUT ;
    USE SIGNAL ;
    PORT
      LAYER Metal2 ;
        RECT  290.2 349.6 290.6 350 ;
    END
  END push_block_i[169]
  PIN push_block_i[16]
    DIRECTION INPUT ;
    USE SIGNAL ;
    PORT
      LAYER Metal2 ;
        RECT  143.32 349.6 143.72 350 ;
    END
  END push_block_i[16]
  PIN push_block_i[170]
    DIRECTION INPUT ;
    USE SIGNAL ;
    PORT
      LAYER Metal2 ;
        RECT  291.16 349.6 291.56 350 ;
    END
  END push_block_i[170]
  PIN push_block_i[171]
    DIRECTION INPUT ;
    USE SIGNAL ;
    PORT
      LAYER Metal2 ;
        RECT  292.12 349.6 292.52 350 ;
    END
  END push_block_i[171]
  PIN push_block_i[172]
    DIRECTION INPUT ;
    USE SIGNAL ;
    PORT
      LAYER Metal2 ;
        RECT  293.08 349.6 293.48 350 ;
    END
  END push_block_i[172]
  PIN push_block_i[173]
    DIRECTION INPUT ;
    USE SIGNAL ;
    PORT
      LAYER Metal2 ;
        RECT  294.04 349.6 294.44 350 ;
    END
  END push_block_i[173]
  PIN push_block_i[174]
    DIRECTION INPUT ;
    USE SIGNAL ;
    PORT
      LAYER Metal2 ;
        RECT  295 349.6 295.4 350 ;
    END
  END push_block_i[174]
  PIN push_block_i[175]
    DIRECTION INPUT ;
    USE SIGNAL ;
    PORT
      LAYER Metal2 ;
        RECT  295.96 349.6 296.36 350 ;
    END
  END push_block_i[175]
  PIN push_block_i[176]
    DIRECTION INPUT ;
    USE SIGNAL ;
    PORT
      LAYER Metal2 ;
        RECT  296.92 349.6 297.32 350 ;
    END
  END push_block_i[176]
  PIN push_block_i[177]
    DIRECTION INPUT ;
    USE SIGNAL ;
    PORT
      LAYER Metal2 ;
        RECT  297.88 349.6 298.28 350 ;
    END
  END push_block_i[177]
  PIN push_block_i[178]
    DIRECTION INPUT ;
    USE SIGNAL ;
    PORT
      LAYER Metal2 ;
        RECT  298.84 349.6 299.24 350 ;
    END
  END push_block_i[178]
  PIN push_block_i[179]
    DIRECTION INPUT ;
    USE SIGNAL ;
    PORT
      LAYER Metal2 ;
        RECT  299.8 349.6 300.2 350 ;
    END
  END push_block_i[179]
  PIN push_block_i[17]
    DIRECTION INPUT ;
    USE SIGNAL ;
    PORT
      LAYER Metal2 ;
        RECT  144.28 349.6 144.68 350 ;
    END
  END push_block_i[17]
  PIN push_block_i[180]
    DIRECTION INPUT ;
    USE SIGNAL ;
    PORT
      LAYER Metal2 ;
        RECT  300.76 349.6 301.16 350 ;
    END
  END push_block_i[180]
  PIN push_block_i[181]
    DIRECTION INPUT ;
    USE SIGNAL ;
    PORT
      LAYER Metal2 ;
        RECT  301.72 349.6 302.12 350 ;
    END
  END push_block_i[181]
  PIN push_block_i[182]
    DIRECTION INPUT ;
    USE SIGNAL ;
    PORT
      LAYER Metal2 ;
        RECT  302.68 349.6 303.08 350 ;
    END
  END push_block_i[182]
  PIN push_block_i[183]
    DIRECTION INPUT ;
    USE SIGNAL ;
    PORT
      LAYER Metal2 ;
        RECT  303.64 349.6 304.04 350 ;
    END
  END push_block_i[183]
  PIN push_block_i[184]
    DIRECTION INPUT ;
    USE SIGNAL ;
    PORT
      LAYER Metal2 ;
        RECT  304.6 349.6 305 350 ;
    END
  END push_block_i[184]
  PIN push_block_i[185]
    DIRECTION INPUT ;
    USE SIGNAL ;
    PORT
      LAYER Metal2 ;
        RECT  305.56 349.6 305.96 350 ;
    END
  END push_block_i[185]
  PIN push_block_i[186]
    DIRECTION INPUT ;
    USE SIGNAL ;
    PORT
      LAYER Metal2 ;
        RECT  306.52 349.6 306.92 350 ;
    END
  END push_block_i[186]
  PIN push_block_i[187]
    DIRECTION INPUT ;
    USE SIGNAL ;
    PORT
      LAYER Metal2 ;
        RECT  307.48 349.6 307.88 350 ;
    END
  END push_block_i[187]
  PIN push_block_i[188]
    DIRECTION INPUT ;
    USE SIGNAL ;
    PORT
      LAYER Metal2 ;
        RECT  308.44 349.6 308.84 350 ;
    END
  END push_block_i[188]
  PIN push_block_i[189]
    DIRECTION INPUT ;
    USE SIGNAL ;
    PORT
      LAYER Metal2 ;
        RECT  309.4 349.6 309.8 350 ;
    END
  END push_block_i[189]
  PIN push_block_i[18]
    DIRECTION INPUT ;
    USE SIGNAL ;
    PORT
      LAYER Metal2 ;
        RECT  145.24 349.6 145.64 350 ;
    END
  END push_block_i[18]
  PIN push_block_i[190]
    DIRECTION INPUT ;
    USE SIGNAL ;
    PORT
      LAYER Metal2 ;
        RECT  310.36 349.6 310.76 350 ;
    END
  END push_block_i[190]
  PIN push_block_i[191]
    DIRECTION INPUT ;
    USE SIGNAL ;
    PORT
      LAYER Metal2 ;
        RECT  311.32 349.6 311.72 350 ;
    END
  END push_block_i[191]
  PIN push_block_i[192]
    DIRECTION INPUT ;
    USE SIGNAL ;
    PORT
      LAYER Metal2 ;
        RECT  312.28 349.6 312.68 350 ;
    END
  END push_block_i[192]
  PIN push_block_i[193]
    DIRECTION INPUT ;
    USE SIGNAL ;
    PORT
      LAYER Metal2 ;
        RECT  313.24 349.6 313.64 350 ;
    END
  END push_block_i[193]
  PIN push_block_i[194]
    DIRECTION INPUT ;
    USE SIGNAL ;
    PORT
      LAYER Metal2 ;
        RECT  314.2 349.6 314.6 350 ;
    END
  END push_block_i[194]
  PIN push_block_i[195]
    DIRECTION INPUT ;
    USE SIGNAL ;
    PORT
      LAYER Metal2 ;
        RECT  315.16 349.6 315.56 350 ;
    END
  END push_block_i[195]
  PIN push_block_i[196]
    DIRECTION INPUT ;
    USE SIGNAL ;
    PORT
      LAYER Metal2 ;
        RECT  316.12 349.6 316.52 350 ;
    END
  END push_block_i[196]
  PIN push_block_i[197]
    DIRECTION INPUT ;
    USE SIGNAL ;
    PORT
      LAYER Metal2 ;
        RECT  317.08 349.6 317.48 350 ;
    END
  END push_block_i[197]
  PIN push_block_i[198]
    DIRECTION INPUT ;
    USE SIGNAL ;
    PORT
      LAYER Metal2 ;
        RECT  318.04 349.6 318.44 350 ;
    END
  END push_block_i[198]
  PIN push_block_i[199]
    DIRECTION INPUT ;
    USE SIGNAL ;
    PORT
      LAYER Metal2 ;
        RECT  319 349.6 319.4 350 ;
    END
  END push_block_i[199]
  PIN push_block_i[19]
    DIRECTION INPUT ;
    USE SIGNAL ;
    PORT
      LAYER Metal2 ;
        RECT  146.2 349.6 146.6 350 ;
    END
  END push_block_i[19]
  PIN push_block_i[1]
    DIRECTION INPUT ;
    USE SIGNAL ;
    PORT
      LAYER Metal2 ;
        RECT  128.92 349.6 129.32 350 ;
    END
  END push_block_i[1]
  PIN push_block_i[200]
    DIRECTION INPUT ;
    USE SIGNAL ;
    PORT
      LAYER Metal2 ;
        RECT  319.96 349.6 320.36 350 ;
    END
  END push_block_i[200]
  PIN push_block_i[201]
    DIRECTION INPUT ;
    USE SIGNAL ;
    PORT
      LAYER Metal2 ;
        RECT  320.92 349.6 321.32 350 ;
    END
  END push_block_i[201]
  PIN push_block_i[202]
    DIRECTION INPUT ;
    USE SIGNAL ;
    PORT
      LAYER Metal2 ;
        RECT  321.88 349.6 322.28 350 ;
    END
  END push_block_i[202]
  PIN push_block_i[203]
    DIRECTION INPUT ;
    USE SIGNAL ;
    PORT
      LAYER Metal2 ;
        RECT  322.84 349.6 323.24 350 ;
    END
  END push_block_i[203]
  PIN push_block_i[204]
    DIRECTION INPUT ;
    USE SIGNAL ;
    PORT
      LAYER Metal2 ;
        RECT  323.8 349.6 324.2 350 ;
    END
  END push_block_i[204]
  PIN push_block_i[205]
    DIRECTION INPUT ;
    USE SIGNAL ;
    PORT
      LAYER Metal2 ;
        RECT  324.76 349.6 325.16 350 ;
    END
  END push_block_i[205]
  PIN push_block_i[206]
    DIRECTION INPUT ;
    USE SIGNAL ;
    PORT
      LAYER Metal2 ;
        RECT  325.72 349.6 326.12 350 ;
    END
  END push_block_i[206]
  PIN push_block_i[207]
    DIRECTION INPUT ;
    USE SIGNAL ;
    PORT
      LAYER Metal2 ;
        RECT  326.68 349.6 327.08 350 ;
    END
  END push_block_i[207]
  PIN push_block_i[208]
    DIRECTION INPUT ;
    USE SIGNAL ;
    PORT
      LAYER Metal2 ;
        RECT  327.64 349.6 328.04 350 ;
    END
  END push_block_i[208]
  PIN push_block_i[209]
    DIRECTION INPUT ;
    USE SIGNAL ;
    PORT
      LAYER Metal2 ;
        RECT  328.6 349.6 329 350 ;
    END
  END push_block_i[209]
  PIN push_block_i[20]
    DIRECTION INPUT ;
    USE SIGNAL ;
    PORT
      LAYER Metal2 ;
        RECT  147.16 349.6 147.56 350 ;
    END
  END push_block_i[20]
  PIN push_block_i[210]
    DIRECTION INPUT ;
    USE SIGNAL ;
    PORT
      LAYER Metal2 ;
        RECT  329.56 349.6 329.96 350 ;
    END
  END push_block_i[210]
  PIN push_block_i[211]
    DIRECTION INPUT ;
    USE SIGNAL ;
    PORT
      LAYER Metal2 ;
        RECT  330.52 349.6 330.92 350 ;
    END
  END push_block_i[211]
  PIN push_block_i[212]
    DIRECTION INPUT ;
    USE SIGNAL ;
    PORT
      LAYER Metal2 ;
        RECT  331.48 349.6 331.88 350 ;
    END
  END push_block_i[212]
  PIN push_block_i[213]
    DIRECTION INPUT ;
    USE SIGNAL ;
    PORT
      LAYER Metal2 ;
        RECT  332.44 349.6 332.84 350 ;
    END
  END push_block_i[213]
  PIN push_block_i[214]
    DIRECTION INPUT ;
    USE SIGNAL ;
    PORT
      LAYER Metal2 ;
        RECT  333.4 349.6 333.8 350 ;
    END
  END push_block_i[214]
  PIN push_block_i[215]
    DIRECTION INPUT ;
    USE SIGNAL ;
    PORT
      LAYER Metal2 ;
        RECT  334.36 349.6 334.76 350 ;
    END
  END push_block_i[215]
  PIN push_block_i[216]
    DIRECTION INPUT ;
    USE SIGNAL ;
    PORT
      LAYER Metal2 ;
        RECT  335.32 349.6 335.72 350 ;
    END
  END push_block_i[216]
  PIN push_block_i[217]
    DIRECTION INPUT ;
    USE SIGNAL ;
    PORT
      LAYER Metal2 ;
        RECT  336.28 349.6 336.68 350 ;
    END
  END push_block_i[217]
  PIN push_block_i[218]
    DIRECTION INPUT ;
    USE SIGNAL ;
    PORT
      LAYER Metal2 ;
        RECT  337.24 349.6 337.64 350 ;
    END
  END push_block_i[218]
  PIN push_block_i[219]
    DIRECTION INPUT ;
    USE SIGNAL ;
    PORT
      LAYER Metal2 ;
        RECT  338.2 349.6 338.6 350 ;
    END
  END push_block_i[219]
  PIN push_block_i[21]
    DIRECTION INPUT ;
    USE SIGNAL ;
    PORT
      LAYER Metal2 ;
        RECT  148.12 349.6 148.52 350 ;
    END
  END push_block_i[21]
  PIN push_block_i[220]
    DIRECTION INPUT ;
    USE SIGNAL ;
    PORT
      LAYER Metal2 ;
        RECT  339.16 349.6 339.56 350 ;
    END
  END push_block_i[220]
  PIN push_block_i[221]
    DIRECTION INPUT ;
    USE SIGNAL ;
    PORT
      LAYER Metal2 ;
        RECT  340.12 349.6 340.52 350 ;
    END
  END push_block_i[221]
  PIN push_block_i[222]
    DIRECTION INPUT ;
    USE SIGNAL ;
    PORT
      LAYER Metal2 ;
        RECT  341.08 349.6 341.48 350 ;
    END
  END push_block_i[222]
  PIN push_block_i[223]
    DIRECTION INPUT ;
    USE SIGNAL ;
    PORT
      LAYER Metal2 ;
        RECT  342.04 349.6 342.44 350 ;
    END
  END push_block_i[223]
  PIN push_block_i[224]
    DIRECTION INPUT ;
    USE SIGNAL ;
    PORT
      LAYER Metal2 ;
        RECT  343 349.6 343.4 350 ;
    END
  END push_block_i[224]
  PIN push_block_i[225]
    DIRECTION INPUT ;
    USE SIGNAL ;
    PORT
      LAYER Metal2 ;
        RECT  343.96 349.6 344.36 350 ;
    END
  END push_block_i[225]
  PIN push_block_i[226]
    DIRECTION INPUT ;
    USE SIGNAL ;
    PORT
      LAYER Metal2 ;
        RECT  344.92 349.6 345.32 350 ;
    END
  END push_block_i[226]
  PIN push_block_i[227]
    DIRECTION INPUT ;
    USE SIGNAL ;
    PORT
      LAYER Metal2 ;
        RECT  345.88 349.6 346.28 350 ;
    END
  END push_block_i[227]
  PIN push_block_i[228]
    DIRECTION INPUT ;
    USE SIGNAL ;
    PORT
      LAYER Metal2 ;
        RECT  346.84 349.6 347.24 350 ;
    END
  END push_block_i[228]
  PIN push_block_i[229]
    DIRECTION INPUT ;
    USE SIGNAL ;
    PORT
      LAYER Metal2 ;
        RECT  347.8 349.6 348.2 350 ;
    END
  END push_block_i[229]
  PIN push_block_i[22]
    DIRECTION INPUT ;
    USE SIGNAL ;
    PORT
      LAYER Metal2 ;
        RECT  149.08 349.6 149.48 350 ;
    END
  END push_block_i[22]
  PIN push_block_i[230]
    DIRECTION INPUT ;
    USE SIGNAL ;
    PORT
      LAYER Metal2 ;
        RECT  348.76 349.6 349.16 350 ;
    END
  END push_block_i[230]
  PIN push_block_i[231]
    DIRECTION INPUT ;
    USE SIGNAL ;
    PORT
      LAYER Metal2 ;
        RECT  349.72 349.6 350.12 350 ;
    END
  END push_block_i[231]
  PIN push_block_i[232]
    DIRECTION INPUT ;
    USE SIGNAL ;
    PORT
      LAYER Metal2 ;
        RECT  350.68 349.6 351.08 350 ;
    END
  END push_block_i[232]
  PIN push_block_i[233]
    DIRECTION INPUT ;
    USE SIGNAL ;
    PORT
      LAYER Metal2 ;
        RECT  351.64 349.6 352.04 350 ;
    END
  END push_block_i[233]
  PIN push_block_i[234]
    DIRECTION INPUT ;
    USE SIGNAL ;
    PORT
      LAYER Metal2 ;
        RECT  352.6 349.6 353 350 ;
    END
  END push_block_i[234]
  PIN push_block_i[235]
    DIRECTION INPUT ;
    USE SIGNAL ;
    PORT
      LAYER Metal2 ;
        RECT  353.56 349.6 353.96 350 ;
    END
  END push_block_i[235]
  PIN push_block_i[236]
    DIRECTION INPUT ;
    USE SIGNAL ;
    PORT
      LAYER Metal2 ;
        RECT  354.52 349.6 354.92 350 ;
    END
  END push_block_i[236]
  PIN push_block_i[237]
    DIRECTION INPUT ;
    USE SIGNAL ;
    PORT
      LAYER Metal2 ;
        RECT  355.48 349.6 355.88 350 ;
    END
  END push_block_i[237]
  PIN push_block_i[238]
    DIRECTION INPUT ;
    USE SIGNAL ;
    PORT
      LAYER Metal2 ;
        RECT  356.44 349.6 356.84 350 ;
    END
  END push_block_i[238]
  PIN push_block_i[239]
    DIRECTION INPUT ;
    USE SIGNAL ;
    PORT
      LAYER Metal2 ;
        RECT  357.4 349.6 357.8 350 ;
    END
  END push_block_i[239]
  PIN push_block_i[23]
    DIRECTION INPUT ;
    USE SIGNAL ;
    PORT
      LAYER Metal2 ;
        RECT  150.04 349.6 150.44 350 ;
    END
  END push_block_i[23]
  PIN push_block_i[240]
    DIRECTION INPUT ;
    USE SIGNAL ;
    PORT
      LAYER Metal2 ;
        RECT  358.36 349.6 358.76 350 ;
    END
  END push_block_i[240]
  PIN push_block_i[241]
    DIRECTION INPUT ;
    USE SIGNAL ;
    PORT
      LAYER Metal2 ;
        RECT  359.32 349.6 359.72 350 ;
    END
  END push_block_i[241]
  PIN push_block_i[242]
    DIRECTION INPUT ;
    USE SIGNAL ;
    PORT
      LAYER Metal2 ;
        RECT  360.28 349.6 360.68 350 ;
    END
  END push_block_i[242]
  PIN push_block_i[243]
    DIRECTION INPUT ;
    USE SIGNAL ;
    PORT
      LAYER Metal2 ;
        RECT  361.24 349.6 361.64 350 ;
    END
  END push_block_i[243]
  PIN push_block_i[244]
    DIRECTION INPUT ;
    USE SIGNAL ;
    PORT
      LAYER Metal2 ;
        RECT  362.2 349.6 362.6 350 ;
    END
  END push_block_i[244]
  PIN push_block_i[245]
    DIRECTION INPUT ;
    USE SIGNAL ;
    PORT
      LAYER Metal2 ;
        RECT  363.16 349.6 363.56 350 ;
    END
  END push_block_i[245]
  PIN push_block_i[246]
    DIRECTION INPUT ;
    USE SIGNAL ;
    PORT
      LAYER Metal2 ;
        RECT  364.12 349.6 364.52 350 ;
    END
  END push_block_i[246]
  PIN push_block_i[247]
    DIRECTION INPUT ;
    USE SIGNAL ;
    PORT
      LAYER Metal2 ;
        RECT  365.08 349.6 365.48 350 ;
    END
  END push_block_i[247]
  PIN push_block_i[248]
    DIRECTION INPUT ;
    USE SIGNAL ;
    PORT
      LAYER Metal2 ;
        RECT  366.04 349.6 366.44 350 ;
    END
  END push_block_i[248]
  PIN push_block_i[249]
    DIRECTION INPUT ;
    USE SIGNAL ;
    PORT
      LAYER Metal2 ;
        RECT  367 349.6 367.4 350 ;
    END
  END push_block_i[249]
  PIN push_block_i[24]
    DIRECTION INPUT ;
    USE SIGNAL ;
    PORT
      LAYER Metal2 ;
        RECT  151 349.6 151.4 350 ;
    END
  END push_block_i[24]
  PIN push_block_i[250]
    DIRECTION INPUT ;
    USE SIGNAL ;
    PORT
      LAYER Metal2 ;
        RECT  367.96 349.6 368.36 350 ;
    END
  END push_block_i[250]
  PIN push_block_i[251]
    DIRECTION INPUT ;
    USE SIGNAL ;
    PORT
      LAYER Metal2 ;
        RECT  368.92 349.6 369.32 350 ;
    END
  END push_block_i[251]
  PIN push_block_i[252]
    DIRECTION INPUT ;
    USE SIGNAL ;
    PORT
      LAYER Metal2 ;
        RECT  369.88 349.6 370.28 350 ;
    END
  END push_block_i[252]
  PIN push_block_i[253]
    DIRECTION INPUT ;
    USE SIGNAL ;
    PORT
      LAYER Metal2 ;
        RECT  370.84 349.6 371.24 350 ;
    END
  END push_block_i[253]
  PIN push_block_i[254]
    DIRECTION INPUT ;
    USE SIGNAL ;
    PORT
      LAYER Metal2 ;
        RECT  371.8 349.6 372.2 350 ;
    END
  END push_block_i[254]
  PIN push_block_i[255]
    DIRECTION INPUT ;
    USE SIGNAL ;
    PORT
      LAYER Metal2 ;
        RECT  372.76 349.6 373.16 350 ;
    END
  END push_block_i[255]
  PIN push_block_i[256]
    DIRECTION INPUT ;
    USE SIGNAL ;
    PORT
      LAYER Metal2 ;
        RECT  373.72 349.6 374.12 350 ;
    END
  END push_block_i[256]
  PIN push_block_i[257]
    DIRECTION INPUT ;
    USE SIGNAL ;
    PORT
      LAYER Metal2 ;
        RECT  374.68 349.6 375.08 350 ;
    END
  END push_block_i[257]
  PIN push_block_i[258]
    DIRECTION INPUT ;
    USE SIGNAL ;
    PORT
      LAYER Metal2 ;
        RECT  375.64 349.6 376.04 350 ;
    END
  END push_block_i[258]
  PIN push_block_i[259]
    DIRECTION INPUT ;
    USE SIGNAL ;
    PORT
      LAYER Metal2 ;
        RECT  376.6 349.6 377 350 ;
    END
  END push_block_i[259]
  PIN push_block_i[25]
    DIRECTION INPUT ;
    USE SIGNAL ;
    PORT
      LAYER Metal2 ;
        RECT  151.96 349.6 152.36 350 ;
    END
  END push_block_i[25]
  PIN push_block_i[260]
    DIRECTION INPUT ;
    USE SIGNAL ;
    PORT
      LAYER Metal2 ;
        RECT  377.56 349.6 377.96 350 ;
    END
  END push_block_i[260]
  PIN push_block_i[261]
    DIRECTION INPUT ;
    USE SIGNAL ;
    PORT
      LAYER Metal2 ;
        RECT  378.52 349.6 378.92 350 ;
    END
  END push_block_i[261]
  PIN push_block_i[262]
    DIRECTION INPUT ;
    USE SIGNAL ;
    PORT
      LAYER Metal2 ;
        RECT  379.48 349.6 379.88 350 ;
    END
  END push_block_i[262]
  PIN push_block_i[263]
    DIRECTION INPUT ;
    USE SIGNAL ;
    PORT
      LAYER Metal2 ;
        RECT  380.44 349.6 380.84 350 ;
    END
  END push_block_i[263]
  PIN push_block_i[264]
    DIRECTION INPUT ;
    USE SIGNAL ;
    PORT
      LAYER Metal2 ;
        RECT  381.4 349.6 381.8 350 ;
    END
  END push_block_i[264]
  PIN push_block_i[265]
    DIRECTION INPUT ;
    USE SIGNAL ;
    PORT
      LAYER Metal2 ;
        RECT  382.36 349.6 382.76 350 ;
    END
  END push_block_i[265]
  PIN push_block_i[266]
    DIRECTION INPUT ;
    USE SIGNAL ;
    PORT
      LAYER Metal2 ;
        RECT  383.32 349.6 383.72 350 ;
    END
  END push_block_i[266]
  PIN push_block_i[267]
    DIRECTION INPUT ;
    USE SIGNAL ;
    PORT
      LAYER Metal2 ;
        RECT  384.28 349.6 384.68 350 ;
    END
  END push_block_i[267]
  PIN push_block_i[268]
    DIRECTION INPUT ;
    USE SIGNAL ;
    PORT
      LAYER Metal2 ;
        RECT  385.24 349.6 385.64 350 ;
    END
  END push_block_i[268]
  PIN push_block_i[269]
    DIRECTION INPUT ;
    USE SIGNAL ;
    PORT
      LAYER Metal2 ;
        RECT  386.2 349.6 386.6 350 ;
    END
  END push_block_i[269]
  PIN push_block_i[26]
    DIRECTION INPUT ;
    USE SIGNAL ;
    PORT
      LAYER Metal2 ;
        RECT  152.92 349.6 153.32 350 ;
    END
  END push_block_i[26]
  PIN push_block_i[270]
    DIRECTION INPUT ;
    USE SIGNAL ;
    PORT
      LAYER Metal2 ;
        RECT  387.16 349.6 387.56 350 ;
    END
  END push_block_i[270]
  PIN push_block_i[271]
    DIRECTION INPUT ;
    USE SIGNAL ;
    PORT
      LAYER Metal2 ;
        RECT  388.12 349.6 388.52 350 ;
    END
  END push_block_i[271]
  PIN push_block_i[272]
    DIRECTION INPUT ;
    USE SIGNAL ;
    PORT
      LAYER Metal2 ;
        RECT  389.08 349.6 389.48 350 ;
    END
  END push_block_i[272]
  PIN push_block_i[273]
    DIRECTION INPUT ;
    USE SIGNAL ;
    PORT
      LAYER Metal2 ;
        RECT  390.04 349.6 390.44 350 ;
    END
  END push_block_i[273]
  PIN push_block_i[274]
    DIRECTION INPUT ;
    USE SIGNAL ;
    PORT
      LAYER Metal2 ;
        RECT  391 349.6 391.4 350 ;
    END
  END push_block_i[274]
  PIN push_block_i[275]
    DIRECTION INPUT ;
    USE SIGNAL ;
    PORT
      LAYER Metal2 ;
        RECT  391.96 349.6 392.36 350 ;
    END
  END push_block_i[275]
  PIN push_block_i[276]
    DIRECTION INPUT ;
    USE SIGNAL ;
    PORT
      LAYER Metal2 ;
        RECT  392.92 349.6 393.32 350 ;
    END
  END push_block_i[276]
  PIN push_block_i[277]
    DIRECTION INPUT ;
    USE SIGNAL ;
    PORT
      LAYER Metal2 ;
        RECT  393.88 349.6 394.28 350 ;
    END
  END push_block_i[277]
  PIN push_block_i[278]
    DIRECTION INPUT ;
    USE SIGNAL ;
    PORT
      LAYER Metal2 ;
        RECT  394.84 349.6 395.24 350 ;
    END
  END push_block_i[278]
  PIN push_block_i[279]
    DIRECTION INPUT ;
    USE SIGNAL ;
    PORT
      LAYER Metal2 ;
        RECT  395.8 349.6 396.2 350 ;
    END
  END push_block_i[279]
  PIN push_block_i[27]
    DIRECTION INPUT ;
    USE SIGNAL ;
    PORT
      LAYER Metal2 ;
        RECT  153.88 349.6 154.28 350 ;
    END
  END push_block_i[27]
  PIN push_block_i[280]
    DIRECTION INPUT ;
    USE SIGNAL ;
    PORT
      LAYER Metal2 ;
        RECT  396.76 349.6 397.16 350 ;
    END
  END push_block_i[280]
  PIN push_block_i[281]
    DIRECTION INPUT ;
    USE SIGNAL ;
    PORT
      LAYER Metal2 ;
        RECT  397.72 349.6 398.12 350 ;
    END
  END push_block_i[281]
  PIN push_block_i[282]
    DIRECTION INPUT ;
    USE SIGNAL ;
    PORT
      LAYER Metal2 ;
        RECT  398.68 349.6 399.08 350 ;
    END
  END push_block_i[282]
  PIN push_block_i[283]
    DIRECTION INPUT ;
    USE SIGNAL ;
    PORT
      LAYER Metal2 ;
        RECT  399.64 349.6 400.04 350 ;
    END
  END push_block_i[283]
  PIN push_block_i[284]
    DIRECTION INPUT ;
    USE SIGNAL ;
    PORT
      LAYER Metal2 ;
        RECT  400.6 349.6 401 350 ;
    END
  END push_block_i[284]
  PIN push_block_i[285]
    DIRECTION INPUT ;
    USE SIGNAL ;
    PORT
      LAYER Metal2 ;
        RECT  401.56 349.6 401.96 350 ;
    END
  END push_block_i[285]
  PIN push_block_i[286]
    DIRECTION INPUT ;
    USE SIGNAL ;
    PORT
      LAYER Metal2 ;
        RECT  402.52 349.6 402.92 350 ;
    END
  END push_block_i[286]
  PIN push_block_i[287]
    DIRECTION INPUT ;
    USE SIGNAL ;
    PORT
      LAYER Metal2 ;
        RECT  403.48 349.6 403.88 350 ;
    END
  END push_block_i[287]
  PIN push_block_i[288]
    DIRECTION INPUT ;
    USE SIGNAL ;
    PORT
      LAYER Metal2 ;
        RECT  404.44 349.6 404.84 350 ;
    END
  END push_block_i[288]
  PIN push_block_i[289]
    DIRECTION INPUT ;
    USE SIGNAL ;
    PORT
      LAYER Metal2 ;
        RECT  405.4 349.6 405.8 350 ;
    END
  END push_block_i[289]
  PIN push_block_i[28]
    DIRECTION INPUT ;
    USE SIGNAL ;
    PORT
      LAYER Metal2 ;
        RECT  154.84 349.6 155.24 350 ;
    END
  END push_block_i[28]
  PIN push_block_i[290]
    DIRECTION INPUT ;
    USE SIGNAL ;
    PORT
      LAYER Metal2 ;
        RECT  406.36 349.6 406.76 350 ;
    END
  END push_block_i[290]
  PIN push_block_i[291]
    DIRECTION INPUT ;
    USE SIGNAL ;
    PORT
      LAYER Metal2 ;
        RECT  407.32 349.6 407.72 350 ;
    END
  END push_block_i[291]
  PIN push_block_i[292]
    DIRECTION INPUT ;
    USE SIGNAL ;
    PORT
      LAYER Metal2 ;
        RECT  408.28 349.6 408.68 350 ;
    END
  END push_block_i[292]
  PIN push_block_i[293]
    DIRECTION INPUT ;
    USE SIGNAL ;
    PORT
      LAYER Metal2 ;
        RECT  409.24 349.6 409.64 350 ;
    END
  END push_block_i[293]
  PIN push_block_i[294]
    DIRECTION INPUT ;
    USE SIGNAL ;
    PORT
      LAYER Metal2 ;
        RECT  410.2 349.6 410.6 350 ;
    END
  END push_block_i[294]
  PIN push_block_i[295]
    DIRECTION INPUT ;
    USE SIGNAL ;
    PORT
      LAYER Metal2 ;
        RECT  411.16 349.6 411.56 350 ;
    END
  END push_block_i[295]
  PIN push_block_i[296]
    DIRECTION INPUT ;
    USE SIGNAL ;
    PORT
      LAYER Metal2 ;
        RECT  412.12 349.6 412.52 350 ;
    END
  END push_block_i[296]
  PIN push_block_i[297]
    DIRECTION INPUT ;
    USE SIGNAL ;
    PORT
      LAYER Metal2 ;
        RECT  413.08 349.6 413.48 350 ;
    END
  END push_block_i[297]
  PIN push_block_i[298]
    DIRECTION INPUT ;
    USE SIGNAL ;
    PORT
      LAYER Metal2 ;
        RECT  414.04 349.6 414.44 350 ;
    END
  END push_block_i[298]
  PIN push_block_i[299]
    DIRECTION INPUT ;
    USE SIGNAL ;
    PORT
      LAYER Metal2 ;
        RECT  415 349.6 415.4 350 ;
    END
  END push_block_i[299]
  PIN push_block_i[29]
    DIRECTION INPUT ;
    USE SIGNAL ;
    PORT
      LAYER Metal2 ;
        RECT  155.8 349.6 156.2 350 ;
    END
  END push_block_i[29]
  PIN push_block_i[2]
    DIRECTION INPUT ;
    USE SIGNAL ;
    PORT
      LAYER Metal2 ;
        RECT  129.88 349.6 130.28 350 ;
    END
  END push_block_i[2]
  PIN push_block_i[300]
    DIRECTION INPUT ;
    USE SIGNAL ;
    PORT
      LAYER Metal2 ;
        RECT  415.96 349.6 416.36 350 ;
    END
  END push_block_i[300]
  PIN push_block_i[301]
    DIRECTION INPUT ;
    USE SIGNAL ;
    PORT
      LAYER Metal2 ;
        RECT  416.92 349.6 417.32 350 ;
    END
  END push_block_i[301]
  PIN push_block_i[302]
    DIRECTION INPUT ;
    USE SIGNAL ;
    PORT
      LAYER Metal2 ;
        RECT  417.88 349.6 418.28 350 ;
    END
  END push_block_i[302]
  PIN push_block_i[303]
    DIRECTION INPUT ;
    USE SIGNAL ;
    PORT
      LAYER Metal2 ;
        RECT  418.84 349.6 419.24 350 ;
    END
  END push_block_i[303]
  PIN push_block_i[304]
    DIRECTION INPUT ;
    USE SIGNAL ;
    PORT
      LAYER Metal2 ;
        RECT  419.8 349.6 420.2 350 ;
    END
  END push_block_i[304]
  PIN push_block_i[305]
    DIRECTION INPUT ;
    USE SIGNAL ;
    PORT
      LAYER Metal2 ;
        RECT  420.76 349.6 421.16 350 ;
    END
  END push_block_i[305]
  PIN push_block_i[306]
    DIRECTION INPUT ;
    USE SIGNAL ;
    PORT
      LAYER Metal2 ;
        RECT  421.72 349.6 422.12 350 ;
    END
  END push_block_i[306]
  PIN push_block_i[307]
    DIRECTION INPUT ;
    USE SIGNAL ;
    PORT
      LAYER Metal2 ;
        RECT  422.68 349.6 423.08 350 ;
    END
  END push_block_i[307]
  PIN push_block_i[308]
    DIRECTION INPUT ;
    USE SIGNAL ;
    PORT
      LAYER Metal2 ;
        RECT  423.64 349.6 424.04 350 ;
    END
  END push_block_i[308]
  PIN push_block_i[309]
    DIRECTION INPUT ;
    USE SIGNAL ;
    PORT
      LAYER Metal2 ;
        RECT  424.6 349.6 425 350 ;
    END
  END push_block_i[309]
  PIN push_block_i[30]
    DIRECTION INPUT ;
    USE SIGNAL ;
    PORT
      LAYER Metal2 ;
        RECT  156.76 349.6 157.16 350 ;
    END
  END push_block_i[30]
  PIN push_block_i[310]
    DIRECTION INPUT ;
    USE SIGNAL ;
    PORT
      LAYER Metal2 ;
        RECT  425.56 349.6 425.96 350 ;
    END
  END push_block_i[310]
  PIN push_block_i[311]
    DIRECTION INPUT ;
    USE SIGNAL ;
    PORT
      LAYER Metal2 ;
        RECT  426.52 349.6 426.92 350 ;
    END
  END push_block_i[311]
  PIN push_block_i[312]
    DIRECTION INPUT ;
    USE SIGNAL ;
    PORT
      LAYER Metal2 ;
        RECT  427.48 349.6 427.88 350 ;
    END
  END push_block_i[312]
  PIN push_block_i[313]
    DIRECTION INPUT ;
    USE SIGNAL ;
    PORT
      LAYER Metal2 ;
        RECT  428.44 349.6 428.84 350 ;
    END
  END push_block_i[313]
  PIN push_block_i[314]
    DIRECTION INPUT ;
    USE SIGNAL ;
    PORT
      LAYER Metal2 ;
        RECT  429.4 349.6 429.8 350 ;
    END
  END push_block_i[314]
  PIN push_block_i[315]
    DIRECTION INPUT ;
    USE SIGNAL ;
    PORT
      LAYER Metal2 ;
        RECT  430.36 349.6 430.76 350 ;
    END
  END push_block_i[315]
  PIN push_block_i[316]
    DIRECTION INPUT ;
    USE SIGNAL ;
    PORT
      LAYER Metal2 ;
        RECT  431.32 349.6 431.72 350 ;
    END
  END push_block_i[316]
  PIN push_block_i[317]
    DIRECTION INPUT ;
    USE SIGNAL ;
    PORT
      LAYER Metal2 ;
        RECT  432.28 349.6 432.68 350 ;
    END
  END push_block_i[317]
  PIN push_block_i[318]
    DIRECTION INPUT ;
    USE SIGNAL ;
    PORT
      LAYER Metal2 ;
        RECT  433.24 349.6 433.64 350 ;
    END
  END push_block_i[318]
  PIN push_block_i[319]
    DIRECTION INPUT ;
    USE SIGNAL ;
    PORT
      LAYER Metal2 ;
        RECT  434.2 349.6 434.6 350 ;
    END
  END push_block_i[319]
  PIN push_block_i[31]
    DIRECTION INPUT ;
    USE SIGNAL ;
    PORT
      LAYER Metal2 ;
        RECT  157.72 349.6 158.12 350 ;
    END
  END push_block_i[31]
  PIN push_block_i[320]
    DIRECTION INPUT ;
    USE SIGNAL ;
    PORT
      LAYER Metal2 ;
        RECT  435.16 349.6 435.56 350 ;
    END
  END push_block_i[320]
  PIN push_block_i[321]
    DIRECTION INPUT ;
    USE SIGNAL ;
    PORT
      LAYER Metal2 ;
        RECT  436.12 349.6 436.52 350 ;
    END
  END push_block_i[321]
  PIN push_block_i[322]
    DIRECTION INPUT ;
    USE SIGNAL ;
    PORT
      LAYER Metal2 ;
        RECT  437.08 349.6 437.48 350 ;
    END
  END push_block_i[322]
  PIN push_block_i[323]
    DIRECTION INPUT ;
    USE SIGNAL ;
    PORT
      LAYER Metal2 ;
        RECT  438.04 349.6 438.44 350 ;
    END
  END push_block_i[323]
  PIN push_block_i[324]
    DIRECTION INPUT ;
    USE SIGNAL ;
    PORT
      LAYER Metal2 ;
        RECT  439 349.6 439.4 350 ;
    END
  END push_block_i[324]
  PIN push_block_i[325]
    DIRECTION INPUT ;
    USE SIGNAL ;
    PORT
      LAYER Metal2 ;
        RECT  439.96 349.6 440.36 350 ;
    END
  END push_block_i[325]
  PIN push_block_i[326]
    DIRECTION INPUT ;
    USE SIGNAL ;
    PORT
      LAYER Metal2 ;
        RECT  440.92 349.6 441.32 350 ;
    END
  END push_block_i[326]
  PIN push_block_i[327]
    DIRECTION INPUT ;
    USE SIGNAL ;
    PORT
      LAYER Metal2 ;
        RECT  441.88 349.6 442.28 350 ;
    END
  END push_block_i[327]
  PIN push_block_i[328]
    DIRECTION INPUT ;
    USE SIGNAL ;
    PORT
      LAYER Metal2 ;
        RECT  442.84 349.6 443.24 350 ;
    END
  END push_block_i[328]
  PIN push_block_i[329]
    DIRECTION INPUT ;
    USE SIGNAL ;
    PORT
      LAYER Metal2 ;
        RECT  443.8 349.6 444.2 350 ;
    END
  END push_block_i[329]
  PIN push_block_i[32]
    DIRECTION INPUT ;
    USE SIGNAL ;
    PORT
      LAYER Metal2 ;
        RECT  158.68 349.6 159.08 350 ;
    END
  END push_block_i[32]
  PIN push_block_i[330]
    DIRECTION INPUT ;
    USE SIGNAL ;
    PORT
      LAYER Metal2 ;
        RECT  444.76 349.6 445.16 350 ;
    END
  END push_block_i[330]
  PIN push_block_i[331]
    DIRECTION INPUT ;
    USE SIGNAL ;
    PORT
      LAYER Metal2 ;
        RECT  445.72 349.6 446.12 350 ;
    END
  END push_block_i[331]
  PIN push_block_i[332]
    DIRECTION INPUT ;
    USE SIGNAL ;
    PORT
      LAYER Metal2 ;
        RECT  446.68 349.6 447.08 350 ;
    END
  END push_block_i[332]
  PIN push_block_i[333]
    DIRECTION INPUT ;
    USE SIGNAL ;
    PORT
      LAYER Metal2 ;
        RECT  447.64 349.6 448.04 350 ;
    END
  END push_block_i[333]
  PIN push_block_i[334]
    DIRECTION INPUT ;
    USE SIGNAL ;
    PORT
      LAYER Metal2 ;
        RECT  448.6 349.6 449 350 ;
    END
  END push_block_i[334]
  PIN push_block_i[335]
    DIRECTION INPUT ;
    USE SIGNAL ;
    PORT
      LAYER Metal2 ;
        RECT  449.56 349.6 449.96 350 ;
    END
  END push_block_i[335]
  PIN push_block_i[336]
    DIRECTION INPUT ;
    USE SIGNAL ;
    PORT
      LAYER Metal2 ;
        RECT  450.52 349.6 450.92 350 ;
    END
  END push_block_i[336]
  PIN push_block_i[337]
    DIRECTION INPUT ;
    USE SIGNAL ;
    PORT
      LAYER Metal2 ;
        RECT  451.48 349.6 451.88 350 ;
    END
  END push_block_i[337]
  PIN push_block_i[338]
    DIRECTION INPUT ;
    USE SIGNAL ;
    PORT
      LAYER Metal2 ;
        RECT  452.44 349.6 452.84 350 ;
    END
  END push_block_i[338]
  PIN push_block_i[339]
    DIRECTION INPUT ;
    USE SIGNAL ;
    PORT
      LAYER Metal2 ;
        RECT  453.4 349.6 453.8 350 ;
    END
  END push_block_i[339]
  PIN push_block_i[33]
    DIRECTION INPUT ;
    USE SIGNAL ;
    PORT
      LAYER Metal2 ;
        RECT  159.64 349.6 160.04 350 ;
    END
  END push_block_i[33]
  PIN push_block_i[340]
    DIRECTION INPUT ;
    USE SIGNAL ;
    PORT
      LAYER Metal2 ;
        RECT  454.36 349.6 454.76 350 ;
    END
  END push_block_i[340]
  PIN push_block_i[341]
    DIRECTION INPUT ;
    USE SIGNAL ;
    PORT
      LAYER Metal2 ;
        RECT  455.32 349.6 455.72 350 ;
    END
  END push_block_i[341]
  PIN push_block_i[342]
    DIRECTION INPUT ;
    USE SIGNAL ;
    PORT
      LAYER Metal2 ;
        RECT  456.28 349.6 456.68 350 ;
    END
  END push_block_i[342]
  PIN push_block_i[343]
    DIRECTION INPUT ;
    USE SIGNAL ;
    PORT
      LAYER Metal2 ;
        RECT  457.24 349.6 457.64 350 ;
    END
  END push_block_i[343]
  PIN push_block_i[344]
    DIRECTION INPUT ;
    USE SIGNAL ;
    PORT
      LAYER Metal2 ;
        RECT  458.2 349.6 458.6 350 ;
    END
  END push_block_i[344]
  PIN push_block_i[345]
    DIRECTION INPUT ;
    USE SIGNAL ;
    PORT
      LAYER Metal2 ;
        RECT  459.16 349.6 459.56 350 ;
    END
  END push_block_i[345]
  PIN push_block_i[346]
    DIRECTION INPUT ;
    USE SIGNAL ;
    PORT
      LAYER Metal2 ;
        RECT  460.12 349.6 460.52 350 ;
    END
  END push_block_i[346]
  PIN push_block_i[347]
    DIRECTION INPUT ;
    USE SIGNAL ;
    PORT
      LAYER Metal2 ;
        RECT  461.08 349.6 461.48 350 ;
    END
  END push_block_i[347]
  PIN push_block_i[348]
    DIRECTION INPUT ;
    USE SIGNAL ;
    PORT
      LAYER Metal2 ;
        RECT  462.04 349.6 462.44 350 ;
    END
  END push_block_i[348]
  PIN push_block_i[349]
    DIRECTION INPUT ;
    USE SIGNAL ;
    PORT
      LAYER Metal2 ;
        RECT  463 349.6 463.4 350 ;
    END
  END push_block_i[349]
  PIN push_block_i[34]
    DIRECTION INPUT ;
    USE SIGNAL ;
    PORT
      LAYER Metal2 ;
        RECT  160.6 349.6 161 350 ;
    END
  END push_block_i[34]
  PIN push_block_i[350]
    DIRECTION INPUT ;
    USE SIGNAL ;
    PORT
      LAYER Metal2 ;
        RECT  463.96 349.6 464.36 350 ;
    END
  END push_block_i[350]
  PIN push_block_i[351]
    DIRECTION INPUT ;
    USE SIGNAL ;
    PORT
      LAYER Metal2 ;
        RECT  464.92 349.6 465.32 350 ;
    END
  END push_block_i[351]
  PIN push_block_i[352]
    DIRECTION INPUT ;
    USE SIGNAL ;
    PORT
      LAYER Metal2 ;
        RECT  465.88 349.6 466.28 350 ;
    END
  END push_block_i[352]
  PIN push_block_i[353]
    DIRECTION INPUT ;
    USE SIGNAL ;
    PORT
      LAYER Metal2 ;
        RECT  466.84 349.6 467.24 350 ;
    END
  END push_block_i[353]
  PIN push_block_i[354]
    DIRECTION INPUT ;
    USE SIGNAL ;
    PORT
      LAYER Metal2 ;
        RECT  467.8 349.6 468.2 350 ;
    END
  END push_block_i[354]
  PIN push_block_i[355]
    DIRECTION INPUT ;
    USE SIGNAL ;
    PORT
      LAYER Metal2 ;
        RECT  468.76 349.6 469.16 350 ;
    END
  END push_block_i[355]
  PIN push_block_i[356]
    DIRECTION INPUT ;
    USE SIGNAL ;
    PORT
      LAYER Metal2 ;
        RECT  469.72 349.6 470.12 350 ;
    END
  END push_block_i[356]
  PIN push_block_i[357]
    DIRECTION INPUT ;
    USE SIGNAL ;
    PORT
      LAYER Metal2 ;
        RECT  470.68 349.6 471.08 350 ;
    END
  END push_block_i[357]
  PIN push_block_i[358]
    DIRECTION INPUT ;
    USE SIGNAL ;
    PORT
      LAYER Metal2 ;
        RECT  471.64 349.6 472.04 350 ;
    END
  END push_block_i[358]
  PIN push_block_i[359]
    DIRECTION INPUT ;
    USE SIGNAL ;
    PORT
      LAYER Metal2 ;
        RECT  472.6 349.6 473 350 ;
    END
  END push_block_i[359]
  PIN push_block_i[35]
    DIRECTION INPUT ;
    USE SIGNAL ;
    PORT
      LAYER Metal2 ;
        RECT  161.56 349.6 161.96 350 ;
    END
  END push_block_i[35]
  PIN push_block_i[360]
    DIRECTION INPUT ;
    USE SIGNAL ;
    PORT
      LAYER Metal2 ;
        RECT  473.56 349.6 473.96 350 ;
    END
  END push_block_i[360]
  PIN push_block_i[361]
    DIRECTION INPUT ;
    USE SIGNAL ;
    PORT
      LAYER Metal2 ;
        RECT  474.52 349.6 474.92 350 ;
    END
  END push_block_i[361]
  PIN push_block_i[362]
    DIRECTION INPUT ;
    USE SIGNAL ;
    PORT
      LAYER Metal2 ;
        RECT  475.48 349.6 475.88 350 ;
    END
  END push_block_i[362]
  PIN push_block_i[363]
    DIRECTION INPUT ;
    USE SIGNAL ;
    PORT
      LAYER Metal2 ;
        RECT  476.44 349.6 476.84 350 ;
    END
  END push_block_i[363]
  PIN push_block_i[364]
    DIRECTION INPUT ;
    USE SIGNAL ;
    PORT
      LAYER Metal2 ;
        RECT  477.4 349.6 477.8 350 ;
    END
  END push_block_i[364]
  PIN push_block_i[365]
    DIRECTION INPUT ;
    USE SIGNAL ;
    PORT
      LAYER Metal2 ;
        RECT  478.36 349.6 478.76 350 ;
    END
  END push_block_i[365]
  PIN push_block_i[366]
    DIRECTION INPUT ;
    USE SIGNAL ;
    PORT
      LAYER Metal2 ;
        RECT  479.32 349.6 479.72 350 ;
    END
  END push_block_i[366]
  PIN push_block_i[367]
    DIRECTION INPUT ;
    USE SIGNAL ;
    PORT
      LAYER Metal2 ;
        RECT  480.28 349.6 480.68 350 ;
    END
  END push_block_i[367]
  PIN push_block_i[368]
    DIRECTION INPUT ;
    USE SIGNAL ;
    PORT
      LAYER Metal2 ;
        RECT  481.24 349.6 481.64 350 ;
    END
  END push_block_i[368]
  PIN push_block_i[369]
    DIRECTION INPUT ;
    USE SIGNAL ;
    PORT
      LAYER Metal2 ;
        RECT  482.2 349.6 482.6 350 ;
    END
  END push_block_i[369]
  PIN push_block_i[36]
    DIRECTION INPUT ;
    USE SIGNAL ;
    PORT
      LAYER Metal2 ;
        RECT  162.52 349.6 162.92 350 ;
    END
  END push_block_i[36]
  PIN push_block_i[370]
    DIRECTION INPUT ;
    USE SIGNAL ;
    PORT
      LAYER Metal2 ;
        RECT  483.16 349.6 483.56 350 ;
    END
  END push_block_i[370]
  PIN push_block_i[371]
    DIRECTION INPUT ;
    USE SIGNAL ;
    PORT
      LAYER Metal2 ;
        RECT  484.12 349.6 484.52 350 ;
    END
  END push_block_i[371]
  PIN push_block_i[372]
    DIRECTION INPUT ;
    USE SIGNAL ;
    PORT
      LAYER Metal2 ;
        RECT  485.08 349.6 485.48 350 ;
    END
  END push_block_i[372]
  PIN push_block_i[373]
    DIRECTION INPUT ;
    USE SIGNAL ;
    PORT
      LAYER Metal2 ;
        RECT  486.04 349.6 486.44 350 ;
    END
  END push_block_i[373]
  PIN push_block_i[374]
    DIRECTION INPUT ;
    USE SIGNAL ;
    PORT
      LAYER Metal2 ;
        RECT  487 349.6 487.4 350 ;
    END
  END push_block_i[374]
  PIN push_block_i[375]
    DIRECTION INPUT ;
    USE SIGNAL ;
    PORT
      LAYER Metal2 ;
        RECT  487.96 349.6 488.36 350 ;
    END
  END push_block_i[375]
  PIN push_block_i[376]
    DIRECTION INPUT ;
    USE SIGNAL ;
    PORT
      LAYER Metal2 ;
        RECT  488.92 349.6 489.32 350 ;
    END
  END push_block_i[376]
  PIN push_block_i[377]
    DIRECTION INPUT ;
    USE SIGNAL ;
    PORT
      LAYER Metal2 ;
        RECT  489.88 349.6 490.28 350 ;
    END
  END push_block_i[377]
  PIN push_block_i[378]
    DIRECTION INPUT ;
    USE SIGNAL ;
    PORT
      LAYER Metal2 ;
        RECT  490.84 349.6 491.24 350 ;
    END
  END push_block_i[378]
  PIN push_block_i[379]
    DIRECTION INPUT ;
    USE SIGNAL ;
    PORT
      LAYER Metal2 ;
        RECT  491.8 349.6 492.2 350 ;
    END
  END push_block_i[379]
  PIN push_block_i[37]
    DIRECTION INPUT ;
    USE SIGNAL ;
    PORT
      LAYER Metal2 ;
        RECT  163.48 349.6 163.88 350 ;
    END
  END push_block_i[37]
  PIN push_block_i[380]
    DIRECTION INPUT ;
    USE SIGNAL ;
    PORT
      LAYER Metal2 ;
        RECT  492.76 349.6 493.16 350 ;
    END
  END push_block_i[380]
  PIN push_block_i[381]
    DIRECTION INPUT ;
    USE SIGNAL ;
    PORT
      LAYER Metal2 ;
        RECT  493.72 349.6 494.12 350 ;
    END
  END push_block_i[381]
  PIN push_block_i[382]
    DIRECTION INPUT ;
    USE SIGNAL ;
    PORT
      LAYER Metal2 ;
        RECT  494.68 349.6 495.08 350 ;
    END
  END push_block_i[382]
  PIN push_block_i[383]
    DIRECTION INPUT ;
    USE SIGNAL ;
    PORT
      LAYER Metal2 ;
        RECT  495.64 349.6 496.04 350 ;
    END
  END push_block_i[383]
  PIN push_block_i[384]
    DIRECTION INPUT ;
    USE SIGNAL ;
    PORT
      LAYER Metal2 ;
        RECT  496.6 349.6 497 350 ;
    END
  END push_block_i[384]
  PIN push_block_i[385]
    DIRECTION INPUT ;
    USE SIGNAL ;
    PORT
      LAYER Metal2 ;
        RECT  497.56 349.6 497.96 350 ;
    END
  END push_block_i[385]
  PIN push_block_i[386]
    DIRECTION INPUT ;
    USE SIGNAL ;
    PORT
      LAYER Metal2 ;
        RECT  498.52 349.6 498.92 350 ;
    END
  END push_block_i[386]
  PIN push_block_i[387]
    DIRECTION INPUT ;
    USE SIGNAL ;
    PORT
      LAYER Metal2 ;
        RECT  499.48 349.6 499.88 350 ;
    END
  END push_block_i[387]
  PIN push_block_i[388]
    DIRECTION INPUT ;
    USE SIGNAL ;
    PORT
      LAYER Metal2 ;
        RECT  500.44 349.6 500.84 350 ;
    END
  END push_block_i[388]
  PIN push_block_i[389]
    DIRECTION INPUT ;
    USE SIGNAL ;
    PORT
      LAYER Metal2 ;
        RECT  501.4 349.6 501.8 350 ;
    END
  END push_block_i[389]
  PIN push_block_i[38]
    DIRECTION INPUT ;
    USE SIGNAL ;
    PORT
      LAYER Metal2 ;
        RECT  164.44 349.6 164.84 350 ;
    END
  END push_block_i[38]
  PIN push_block_i[390]
    DIRECTION INPUT ;
    USE SIGNAL ;
    PORT
      LAYER Metal2 ;
        RECT  502.36 349.6 502.76 350 ;
    END
  END push_block_i[390]
  PIN push_block_i[391]
    DIRECTION INPUT ;
    USE SIGNAL ;
    PORT
      LAYER Metal2 ;
        RECT  503.32 349.6 503.72 350 ;
    END
  END push_block_i[391]
  PIN push_block_i[392]
    DIRECTION INPUT ;
    USE SIGNAL ;
    PORT
      LAYER Metal2 ;
        RECT  504.28 349.6 504.68 350 ;
    END
  END push_block_i[392]
  PIN push_block_i[393]
    DIRECTION INPUT ;
    USE SIGNAL ;
    PORT
      LAYER Metal2 ;
        RECT  505.24 349.6 505.64 350 ;
    END
  END push_block_i[393]
  PIN push_block_i[394]
    DIRECTION INPUT ;
    USE SIGNAL ;
    PORT
      LAYER Metal2 ;
        RECT  506.2 349.6 506.6 350 ;
    END
  END push_block_i[394]
  PIN push_block_i[395]
    DIRECTION INPUT ;
    USE SIGNAL ;
    PORT
      LAYER Metal2 ;
        RECT  507.16 349.6 507.56 350 ;
    END
  END push_block_i[395]
  PIN push_block_i[396]
    DIRECTION INPUT ;
    USE SIGNAL ;
    PORT
      LAYER Metal2 ;
        RECT  508.12 349.6 508.52 350 ;
    END
  END push_block_i[396]
  PIN push_block_i[397]
    DIRECTION INPUT ;
    USE SIGNAL ;
    PORT
      LAYER Metal2 ;
        RECT  509.08 349.6 509.48 350 ;
    END
  END push_block_i[397]
  PIN push_block_i[398]
    DIRECTION INPUT ;
    USE SIGNAL ;
    PORT
      LAYER Metal2 ;
        RECT  510.04 349.6 510.44 350 ;
    END
  END push_block_i[398]
  PIN push_block_i[399]
    DIRECTION INPUT ;
    USE SIGNAL ;
    PORT
      LAYER Metal2 ;
        RECT  511 349.6 511.4 350 ;
    END
  END push_block_i[399]
  PIN push_block_i[39]
    DIRECTION INPUT ;
    USE SIGNAL ;
    PORT
      LAYER Metal2 ;
        RECT  165.4 349.6 165.8 350 ;
    END
  END push_block_i[39]
  PIN push_block_i[3]
    DIRECTION INPUT ;
    USE SIGNAL ;
    PORT
      LAYER Metal2 ;
        RECT  130.84 349.6 131.24 350 ;
    END
  END push_block_i[3]
  PIN push_block_i[400]
    DIRECTION INPUT ;
    USE SIGNAL ;
    PORT
      LAYER Metal2 ;
        RECT  511.96 349.6 512.36 350 ;
    END
  END push_block_i[400]
  PIN push_block_i[401]
    DIRECTION INPUT ;
    USE SIGNAL ;
    PORT
      LAYER Metal2 ;
        RECT  512.92 349.6 513.32 350 ;
    END
  END push_block_i[401]
  PIN push_block_i[402]
    DIRECTION INPUT ;
    USE SIGNAL ;
    PORT
      LAYER Metal2 ;
        RECT  513.88 349.6 514.28 350 ;
    END
  END push_block_i[402]
  PIN push_block_i[403]
    DIRECTION INPUT ;
    USE SIGNAL ;
    PORT
      LAYER Metal2 ;
        RECT  514.84 349.6 515.24 350 ;
    END
  END push_block_i[403]
  PIN push_block_i[404]
    DIRECTION INPUT ;
    USE SIGNAL ;
    PORT
      LAYER Metal2 ;
        RECT  515.8 349.6 516.2 350 ;
    END
  END push_block_i[404]
  PIN push_block_i[405]
    DIRECTION INPUT ;
    USE SIGNAL ;
    PORT
      LAYER Metal2 ;
        RECT  516.76 349.6 517.16 350 ;
    END
  END push_block_i[405]
  PIN push_block_i[406]
    DIRECTION INPUT ;
    USE SIGNAL ;
    PORT
      LAYER Metal2 ;
        RECT  517.72 349.6 518.12 350 ;
    END
  END push_block_i[406]
  PIN push_block_i[407]
    DIRECTION INPUT ;
    USE SIGNAL ;
    PORT
      LAYER Metal2 ;
        RECT  518.68 349.6 519.08 350 ;
    END
  END push_block_i[407]
  PIN push_block_i[408]
    DIRECTION INPUT ;
    USE SIGNAL ;
    PORT
      LAYER Metal2 ;
        RECT  519.64 349.6 520.04 350 ;
    END
  END push_block_i[408]
  PIN push_block_i[409]
    DIRECTION INPUT ;
    USE SIGNAL ;
    PORT
      LAYER Metal2 ;
        RECT  520.6 349.6 521 350 ;
    END
  END push_block_i[409]
  PIN push_block_i[40]
    DIRECTION INPUT ;
    USE SIGNAL ;
    PORT
      LAYER Metal2 ;
        RECT  166.36 349.6 166.76 350 ;
    END
  END push_block_i[40]
  PIN push_block_i[410]
    DIRECTION INPUT ;
    USE SIGNAL ;
    PORT
      LAYER Metal2 ;
        RECT  521.56 349.6 521.96 350 ;
    END
  END push_block_i[410]
  PIN push_block_i[411]
    DIRECTION INPUT ;
    USE SIGNAL ;
    PORT
      LAYER Metal2 ;
        RECT  522.52 349.6 522.92 350 ;
    END
  END push_block_i[411]
  PIN push_block_i[412]
    DIRECTION INPUT ;
    USE SIGNAL ;
    PORT
      LAYER Metal2 ;
        RECT  523.48 349.6 523.88 350 ;
    END
  END push_block_i[412]
  PIN push_block_i[413]
    DIRECTION INPUT ;
    USE SIGNAL ;
    PORT
      LAYER Metal2 ;
        RECT  524.44 349.6 524.84 350 ;
    END
  END push_block_i[413]
  PIN push_block_i[414]
    DIRECTION INPUT ;
    USE SIGNAL ;
    PORT
      LAYER Metal2 ;
        RECT  525.4 349.6 525.8 350 ;
    END
  END push_block_i[414]
  PIN push_block_i[415]
    DIRECTION INPUT ;
    USE SIGNAL ;
    PORT
      LAYER Metal2 ;
        RECT  526.36 349.6 526.76 350 ;
    END
  END push_block_i[415]
  PIN push_block_i[416]
    DIRECTION INPUT ;
    USE SIGNAL ;
    PORT
      LAYER Metal2 ;
        RECT  527.32 349.6 527.72 350 ;
    END
  END push_block_i[416]
  PIN push_block_i[417]
    DIRECTION INPUT ;
    USE SIGNAL ;
    PORT
      LAYER Metal2 ;
        RECT  528.28 349.6 528.68 350 ;
    END
  END push_block_i[417]
  PIN push_block_i[418]
    DIRECTION INPUT ;
    USE SIGNAL ;
    PORT
      LAYER Metal2 ;
        RECT  529.24 349.6 529.64 350 ;
    END
  END push_block_i[418]
  PIN push_block_i[419]
    DIRECTION INPUT ;
    USE SIGNAL ;
    PORT
      LAYER Metal2 ;
        RECT  530.2 349.6 530.6 350 ;
    END
  END push_block_i[419]
  PIN push_block_i[41]
    DIRECTION INPUT ;
    USE SIGNAL ;
    PORT
      LAYER Metal2 ;
        RECT  167.32 349.6 167.72 350 ;
    END
  END push_block_i[41]
  PIN push_block_i[420]
    DIRECTION INPUT ;
    USE SIGNAL ;
    PORT
      LAYER Metal2 ;
        RECT  531.16 349.6 531.56 350 ;
    END
  END push_block_i[420]
  PIN push_block_i[421]
    DIRECTION INPUT ;
    USE SIGNAL ;
    PORT
      LAYER Metal2 ;
        RECT  532.12 349.6 532.52 350 ;
    END
  END push_block_i[421]
  PIN push_block_i[422]
    DIRECTION INPUT ;
    USE SIGNAL ;
    PORT
      LAYER Metal2 ;
        RECT  533.08 349.6 533.48 350 ;
    END
  END push_block_i[422]
  PIN push_block_i[423]
    DIRECTION INPUT ;
    USE SIGNAL ;
    PORT
      LAYER Metal2 ;
        RECT  534.04 349.6 534.44 350 ;
    END
  END push_block_i[423]
  PIN push_block_i[424]
    DIRECTION INPUT ;
    USE SIGNAL ;
    PORT
      LAYER Metal2 ;
        RECT  535 349.6 535.4 350 ;
    END
  END push_block_i[424]
  PIN push_block_i[425]
    DIRECTION INPUT ;
    USE SIGNAL ;
    PORT
      LAYER Metal2 ;
        RECT  535.96 349.6 536.36 350 ;
    END
  END push_block_i[425]
  PIN push_block_i[426]
    DIRECTION INPUT ;
    USE SIGNAL ;
    PORT
      LAYER Metal2 ;
        RECT  536.92 349.6 537.32 350 ;
    END
  END push_block_i[426]
  PIN push_block_i[427]
    DIRECTION INPUT ;
    USE SIGNAL ;
    PORT
      LAYER Metal2 ;
        RECT  537.88 349.6 538.28 350 ;
    END
  END push_block_i[427]
  PIN push_block_i[428]
    DIRECTION INPUT ;
    USE SIGNAL ;
    PORT
      LAYER Metal2 ;
        RECT  538.84 349.6 539.24 350 ;
    END
  END push_block_i[428]
  PIN push_block_i[429]
    DIRECTION INPUT ;
    USE SIGNAL ;
    PORT
      LAYER Metal2 ;
        RECT  539.8 349.6 540.2 350 ;
    END
  END push_block_i[429]
  PIN push_block_i[42]
    DIRECTION INPUT ;
    USE SIGNAL ;
    PORT
      LAYER Metal2 ;
        RECT  168.28 349.6 168.68 350 ;
    END
  END push_block_i[42]
  PIN push_block_i[430]
    DIRECTION INPUT ;
    USE SIGNAL ;
    PORT
      LAYER Metal2 ;
        RECT  540.76 349.6 541.16 350 ;
    END
  END push_block_i[430]
  PIN push_block_i[431]
    DIRECTION INPUT ;
    USE SIGNAL ;
    PORT
      LAYER Metal2 ;
        RECT  541.72 349.6 542.12 350 ;
    END
  END push_block_i[431]
  PIN push_block_i[432]
    DIRECTION INPUT ;
    USE SIGNAL ;
    PORT
      LAYER Metal2 ;
        RECT  542.68 349.6 543.08 350 ;
    END
  END push_block_i[432]
  PIN push_block_i[433]
    DIRECTION INPUT ;
    USE SIGNAL ;
    PORT
      LAYER Metal2 ;
        RECT  543.64 349.6 544.04 350 ;
    END
  END push_block_i[433]
  PIN push_block_i[434]
    DIRECTION INPUT ;
    USE SIGNAL ;
    PORT
      LAYER Metal2 ;
        RECT  544.6 349.6 545 350 ;
    END
  END push_block_i[434]
  PIN push_block_i[435]
    DIRECTION INPUT ;
    USE SIGNAL ;
    PORT
      LAYER Metal2 ;
        RECT  545.56 349.6 545.96 350 ;
    END
  END push_block_i[435]
  PIN push_block_i[436]
    DIRECTION INPUT ;
    USE SIGNAL ;
    PORT
      LAYER Metal2 ;
        RECT  546.52 349.6 546.92 350 ;
    END
  END push_block_i[436]
  PIN push_block_i[437]
    DIRECTION INPUT ;
    USE SIGNAL ;
    PORT
      LAYER Metal2 ;
        RECT  547.48 349.6 547.88 350 ;
    END
  END push_block_i[437]
  PIN push_block_i[438]
    DIRECTION INPUT ;
    USE SIGNAL ;
    PORT
      LAYER Metal2 ;
        RECT  548.44 349.6 548.84 350 ;
    END
  END push_block_i[438]
  PIN push_block_i[439]
    DIRECTION INPUT ;
    USE SIGNAL ;
    PORT
      LAYER Metal2 ;
        RECT  549.4 349.6 549.8 350 ;
    END
  END push_block_i[439]
  PIN push_block_i[43]
    DIRECTION INPUT ;
    USE SIGNAL ;
    PORT
      LAYER Metal2 ;
        RECT  169.24 349.6 169.64 350 ;
    END
  END push_block_i[43]
  PIN push_block_i[440]
    DIRECTION INPUT ;
    USE SIGNAL ;
    PORT
      LAYER Metal2 ;
        RECT  550.36 349.6 550.76 350 ;
    END
  END push_block_i[440]
  PIN push_block_i[441]
    DIRECTION INPUT ;
    USE SIGNAL ;
    PORT
      LAYER Metal2 ;
        RECT  551.32 349.6 551.72 350 ;
    END
  END push_block_i[441]
  PIN push_block_i[442]
    DIRECTION INPUT ;
    USE SIGNAL ;
    PORT
      LAYER Metal2 ;
        RECT  552.28 349.6 552.68 350 ;
    END
  END push_block_i[442]
  PIN push_block_i[443]
    DIRECTION INPUT ;
    USE SIGNAL ;
    PORT
      LAYER Metal2 ;
        RECT  553.24 349.6 553.64 350 ;
    END
  END push_block_i[443]
  PIN push_block_i[444]
    DIRECTION INPUT ;
    USE SIGNAL ;
    PORT
      LAYER Metal2 ;
        RECT  554.2 349.6 554.6 350 ;
    END
  END push_block_i[444]
  PIN push_block_i[445]
    DIRECTION INPUT ;
    USE SIGNAL ;
    PORT
      LAYER Metal2 ;
        RECT  555.16 349.6 555.56 350 ;
    END
  END push_block_i[445]
  PIN push_block_i[446]
    DIRECTION INPUT ;
    USE SIGNAL ;
    PORT
      LAYER Metal2 ;
        RECT  556.12 349.6 556.52 350 ;
    END
  END push_block_i[446]
  PIN push_block_i[447]
    DIRECTION INPUT ;
    USE SIGNAL ;
    PORT
      LAYER Metal2 ;
        RECT  557.08 349.6 557.48 350 ;
    END
  END push_block_i[447]
  PIN push_block_i[448]
    DIRECTION INPUT ;
    USE SIGNAL ;
    PORT
      LAYER Metal2 ;
        RECT  558.04 349.6 558.44 350 ;
    END
  END push_block_i[448]
  PIN push_block_i[449]
    DIRECTION INPUT ;
    USE SIGNAL ;
    PORT
      LAYER Metal2 ;
        RECT  559 349.6 559.4 350 ;
    END
  END push_block_i[449]
  PIN push_block_i[44]
    DIRECTION INPUT ;
    USE SIGNAL ;
    PORT
      LAYER Metal2 ;
        RECT  170.2 349.6 170.6 350 ;
    END
  END push_block_i[44]
  PIN push_block_i[450]
    DIRECTION INPUT ;
    USE SIGNAL ;
    PORT
      LAYER Metal2 ;
        RECT  559.96 349.6 560.36 350 ;
    END
  END push_block_i[450]
  PIN push_block_i[451]
    DIRECTION INPUT ;
    USE SIGNAL ;
    PORT
      LAYER Metal2 ;
        RECT  560.92 349.6 561.32 350 ;
    END
  END push_block_i[451]
  PIN push_block_i[452]
    DIRECTION INPUT ;
    USE SIGNAL ;
    PORT
      LAYER Metal2 ;
        RECT  561.88 349.6 562.28 350 ;
    END
  END push_block_i[452]
  PIN push_block_i[453]
    DIRECTION INPUT ;
    USE SIGNAL ;
    PORT
      LAYER Metal2 ;
        RECT  562.84 349.6 563.24 350 ;
    END
  END push_block_i[453]
  PIN push_block_i[454]
    DIRECTION INPUT ;
    USE SIGNAL ;
    PORT
      LAYER Metal2 ;
        RECT  563.8 349.6 564.2 350 ;
    END
  END push_block_i[454]
  PIN push_block_i[455]
    DIRECTION INPUT ;
    USE SIGNAL ;
    PORT
      LAYER Metal2 ;
        RECT  564.76 349.6 565.16 350 ;
    END
  END push_block_i[455]
  PIN push_block_i[456]
    DIRECTION INPUT ;
    USE SIGNAL ;
    PORT
      LAYER Metal2 ;
        RECT  565.72 349.6 566.12 350 ;
    END
  END push_block_i[456]
  PIN push_block_i[457]
    DIRECTION INPUT ;
    USE SIGNAL ;
    PORT
      LAYER Metal2 ;
        RECT  566.68 349.6 567.08 350 ;
    END
  END push_block_i[457]
  PIN push_block_i[458]
    DIRECTION INPUT ;
    USE SIGNAL ;
    PORT
      LAYER Metal2 ;
        RECT  567.64 349.6 568.04 350 ;
    END
  END push_block_i[458]
  PIN push_block_i[459]
    DIRECTION INPUT ;
    USE SIGNAL ;
    PORT
      LAYER Metal2 ;
        RECT  568.6 349.6 569 350 ;
    END
  END push_block_i[459]
  PIN push_block_i[45]
    DIRECTION INPUT ;
    USE SIGNAL ;
    PORT
      LAYER Metal2 ;
        RECT  171.16 349.6 171.56 350 ;
    END
  END push_block_i[45]
  PIN push_block_i[460]
    DIRECTION INPUT ;
    USE SIGNAL ;
    PORT
      LAYER Metal2 ;
        RECT  569.56 349.6 569.96 350 ;
    END
  END push_block_i[460]
  PIN push_block_i[461]
    DIRECTION INPUT ;
    USE SIGNAL ;
    PORT
      LAYER Metal2 ;
        RECT  570.52 349.6 570.92 350 ;
    END
  END push_block_i[461]
  PIN push_block_i[462]
    DIRECTION INPUT ;
    USE SIGNAL ;
    PORT
      LAYER Metal2 ;
        RECT  571.48 349.6 571.88 350 ;
    END
  END push_block_i[462]
  PIN push_block_i[463]
    DIRECTION INPUT ;
    USE SIGNAL ;
    PORT
      LAYER Metal2 ;
        RECT  572.44 349.6 572.84 350 ;
    END
  END push_block_i[463]
  PIN push_block_i[464]
    DIRECTION INPUT ;
    USE SIGNAL ;
    PORT
      LAYER Metal2 ;
        RECT  573.4 349.6 573.8 350 ;
    END
  END push_block_i[464]
  PIN push_block_i[465]
    DIRECTION INPUT ;
    USE SIGNAL ;
    PORT
      LAYER Metal2 ;
        RECT  574.36 349.6 574.76 350 ;
    END
  END push_block_i[465]
  PIN push_block_i[466]
    DIRECTION INPUT ;
    USE SIGNAL ;
    PORT
      LAYER Metal2 ;
        RECT  575.32 349.6 575.72 350 ;
    END
  END push_block_i[466]
  PIN push_block_i[467]
    DIRECTION INPUT ;
    USE SIGNAL ;
    PORT
      LAYER Metal2 ;
        RECT  576.28 349.6 576.68 350 ;
    END
  END push_block_i[467]
  PIN push_block_i[468]
    DIRECTION INPUT ;
    USE SIGNAL ;
    PORT
      LAYER Metal2 ;
        RECT  577.24 349.6 577.64 350 ;
    END
  END push_block_i[468]
  PIN push_block_i[469]
    DIRECTION INPUT ;
    USE SIGNAL ;
    PORT
      LAYER Metal2 ;
        RECT  578.2 349.6 578.6 350 ;
    END
  END push_block_i[469]
  PIN push_block_i[46]
    DIRECTION INPUT ;
    USE SIGNAL ;
    PORT
      LAYER Metal2 ;
        RECT  172.12 349.6 172.52 350 ;
    END
  END push_block_i[46]
  PIN push_block_i[470]
    DIRECTION INPUT ;
    USE SIGNAL ;
    PORT
      LAYER Metal2 ;
        RECT  579.16 349.6 579.56 350 ;
    END
  END push_block_i[470]
  PIN push_block_i[471]
    DIRECTION INPUT ;
    USE SIGNAL ;
    PORT
      LAYER Metal2 ;
        RECT  580.12 349.6 580.52 350 ;
    END
  END push_block_i[471]
  PIN push_block_i[472]
    DIRECTION INPUT ;
    USE SIGNAL ;
    PORT
      LAYER Metal2 ;
        RECT  581.08 349.6 581.48 350 ;
    END
  END push_block_i[472]
  PIN push_block_i[473]
    DIRECTION INPUT ;
    USE SIGNAL ;
    PORT
      LAYER Metal2 ;
        RECT  582.04 349.6 582.44 350 ;
    END
  END push_block_i[473]
  PIN push_block_i[474]
    DIRECTION INPUT ;
    USE SIGNAL ;
    PORT
      LAYER Metal2 ;
        RECT  583 349.6 583.4 350 ;
    END
  END push_block_i[474]
  PIN push_block_i[475]
    DIRECTION INPUT ;
    USE SIGNAL ;
    PORT
      LAYER Metal2 ;
        RECT  583.96 349.6 584.36 350 ;
    END
  END push_block_i[475]
  PIN push_block_i[476]
    DIRECTION INPUT ;
    USE SIGNAL ;
    PORT
      LAYER Metal2 ;
        RECT  584.92 349.6 585.32 350 ;
    END
  END push_block_i[476]
  PIN push_block_i[477]
    DIRECTION INPUT ;
    USE SIGNAL ;
    PORT
      LAYER Metal2 ;
        RECT  585.88 349.6 586.28 350 ;
    END
  END push_block_i[477]
  PIN push_block_i[478]
    DIRECTION INPUT ;
    USE SIGNAL ;
    PORT
      LAYER Metal2 ;
        RECT  586.84 349.6 587.24 350 ;
    END
  END push_block_i[478]
  PIN push_block_i[479]
    DIRECTION INPUT ;
    USE SIGNAL ;
    PORT
      LAYER Metal2 ;
        RECT  587.8 349.6 588.2 350 ;
    END
  END push_block_i[479]
  PIN push_block_i[47]
    DIRECTION INPUT ;
    USE SIGNAL ;
    PORT
      LAYER Metal2 ;
        RECT  173.08 349.6 173.48 350 ;
    END
  END push_block_i[47]
  PIN push_block_i[480]
    DIRECTION INPUT ;
    USE SIGNAL ;
    PORT
      LAYER Metal2 ;
        RECT  588.76 349.6 589.16 350 ;
    END
  END push_block_i[480]
  PIN push_block_i[481]
    DIRECTION INPUT ;
    USE SIGNAL ;
    PORT
      LAYER Metal2 ;
        RECT  589.72 349.6 590.12 350 ;
    END
  END push_block_i[481]
  PIN push_block_i[482]
    DIRECTION INPUT ;
    USE SIGNAL ;
    PORT
      LAYER Metal2 ;
        RECT  590.68 349.6 591.08 350 ;
    END
  END push_block_i[482]
  PIN push_block_i[483]
    DIRECTION INPUT ;
    USE SIGNAL ;
    PORT
      LAYER Metal2 ;
        RECT  591.64 349.6 592.04 350 ;
    END
  END push_block_i[483]
  PIN push_block_i[484]
    DIRECTION INPUT ;
    USE SIGNAL ;
    PORT
      LAYER Metal2 ;
        RECT  592.6 349.6 593 350 ;
    END
  END push_block_i[484]
  PIN push_block_i[485]
    DIRECTION INPUT ;
    USE SIGNAL ;
    PORT
      LAYER Metal2 ;
        RECT  593.56 349.6 593.96 350 ;
    END
  END push_block_i[485]
  PIN push_block_i[486]
    DIRECTION INPUT ;
    USE SIGNAL ;
    PORT
      LAYER Metal2 ;
        RECT  594.52 349.6 594.92 350 ;
    END
  END push_block_i[486]
  PIN push_block_i[487]
    DIRECTION INPUT ;
    USE SIGNAL ;
    PORT
      LAYER Metal2 ;
        RECT  595.48 349.6 595.88 350 ;
    END
  END push_block_i[487]
  PIN push_block_i[488]
    DIRECTION INPUT ;
    USE SIGNAL ;
    PORT
      LAYER Metal2 ;
        RECT  596.44 349.6 596.84 350 ;
    END
  END push_block_i[488]
  PIN push_block_i[489]
    DIRECTION INPUT ;
    USE SIGNAL ;
    PORT
      LAYER Metal2 ;
        RECT  597.4 349.6 597.8 350 ;
    END
  END push_block_i[489]
  PIN push_block_i[48]
    DIRECTION INPUT ;
    USE SIGNAL ;
    PORT
      LAYER Metal2 ;
        RECT  174.04 349.6 174.44 350 ;
    END
  END push_block_i[48]
  PIN push_block_i[490]
    DIRECTION INPUT ;
    USE SIGNAL ;
    PORT
      LAYER Metal2 ;
        RECT  598.36 349.6 598.76 350 ;
    END
  END push_block_i[490]
  PIN push_block_i[491]
    DIRECTION INPUT ;
    USE SIGNAL ;
    PORT
      LAYER Metal2 ;
        RECT  599.32 349.6 599.72 350 ;
    END
  END push_block_i[491]
  PIN push_block_i[492]
    DIRECTION INPUT ;
    USE SIGNAL ;
    PORT
      LAYER Metal2 ;
        RECT  600.28 349.6 600.68 350 ;
    END
  END push_block_i[492]
  PIN push_block_i[493]
    DIRECTION INPUT ;
    USE SIGNAL ;
    PORT
      LAYER Metal2 ;
        RECT  601.24 349.6 601.64 350 ;
    END
  END push_block_i[493]
  PIN push_block_i[494]
    DIRECTION INPUT ;
    USE SIGNAL ;
    PORT
      LAYER Metal2 ;
        RECT  602.2 349.6 602.6 350 ;
    END
  END push_block_i[494]
  PIN push_block_i[495]
    DIRECTION INPUT ;
    USE SIGNAL ;
    PORT
      LAYER Metal2 ;
        RECT  603.16 349.6 603.56 350 ;
    END
  END push_block_i[495]
  PIN push_block_i[496]
    DIRECTION INPUT ;
    USE SIGNAL ;
    PORT
      LAYER Metal2 ;
        RECT  604.12 349.6 604.52 350 ;
    END
  END push_block_i[496]
  PIN push_block_i[497]
    DIRECTION INPUT ;
    USE SIGNAL ;
    PORT
      LAYER Metal2 ;
        RECT  605.08 349.6 605.48 350 ;
    END
  END push_block_i[497]
  PIN push_block_i[498]
    DIRECTION INPUT ;
    USE SIGNAL ;
    PORT
      LAYER Metal2 ;
        RECT  606.04 349.6 606.44 350 ;
    END
  END push_block_i[498]
  PIN push_block_i[499]
    DIRECTION INPUT ;
    USE SIGNAL ;
    PORT
      LAYER Metal2 ;
        RECT  607 349.6 607.4 350 ;
    END
  END push_block_i[499]
  PIN push_block_i[49]
    DIRECTION INPUT ;
    USE SIGNAL ;
    PORT
      LAYER Metal2 ;
        RECT  175 349.6 175.4 350 ;
    END
  END push_block_i[49]
  PIN push_block_i[4]
    DIRECTION INPUT ;
    USE SIGNAL ;
    PORT
      LAYER Metal2 ;
        RECT  131.8 349.6 132.2 350 ;
    END
  END push_block_i[4]
  PIN push_block_i[500]
    DIRECTION INPUT ;
    USE SIGNAL ;
    PORT
      LAYER Metal2 ;
        RECT  607.96 349.6 608.36 350 ;
    END
  END push_block_i[500]
  PIN push_block_i[501]
    DIRECTION INPUT ;
    USE SIGNAL ;
    PORT
      LAYER Metal2 ;
        RECT  608.92 349.6 609.32 350 ;
    END
  END push_block_i[501]
  PIN push_block_i[502]
    DIRECTION INPUT ;
    USE SIGNAL ;
    PORT
      LAYER Metal2 ;
        RECT  609.88 349.6 610.28 350 ;
    END
  END push_block_i[502]
  PIN push_block_i[503]
    DIRECTION INPUT ;
    USE SIGNAL ;
    PORT
      LAYER Metal2 ;
        RECT  610.84 349.6 611.24 350 ;
    END
  END push_block_i[503]
  PIN push_block_i[504]
    DIRECTION INPUT ;
    USE SIGNAL ;
    PORT
      LAYER Metal2 ;
        RECT  611.8 349.6 612.2 350 ;
    END
  END push_block_i[504]
  PIN push_block_i[505]
    DIRECTION INPUT ;
    USE SIGNAL ;
    PORT
      LAYER Metal2 ;
        RECT  612.76 349.6 613.16 350 ;
    END
  END push_block_i[505]
  PIN push_block_i[506]
    DIRECTION INPUT ;
    USE SIGNAL ;
    PORT
      LAYER Metal2 ;
        RECT  613.72 349.6 614.12 350 ;
    END
  END push_block_i[506]
  PIN push_block_i[507]
    DIRECTION INPUT ;
    USE SIGNAL ;
    PORT
      LAYER Metal2 ;
        RECT  614.68 349.6 615.08 350 ;
    END
  END push_block_i[507]
  PIN push_block_i[508]
    DIRECTION INPUT ;
    USE SIGNAL ;
    PORT
      LAYER Metal2 ;
        RECT  615.64 349.6 616.04 350 ;
    END
  END push_block_i[508]
  PIN push_block_i[509]
    DIRECTION INPUT ;
    USE SIGNAL ;
    PORT
      LAYER Metal2 ;
        RECT  616.6 349.6 617 350 ;
    END
  END push_block_i[509]
  PIN push_block_i[50]
    DIRECTION INPUT ;
    USE SIGNAL ;
    PORT
      LAYER Metal2 ;
        RECT  175.96 349.6 176.36 350 ;
    END
  END push_block_i[50]
  PIN push_block_i[510]
    DIRECTION INPUT ;
    USE SIGNAL ;
    PORT
      LAYER Metal2 ;
        RECT  617.56 349.6 617.96 350 ;
    END
  END push_block_i[510]
  PIN push_block_i[511]
    DIRECTION INPUT ;
    USE SIGNAL ;
    PORT
      LAYER Metal2 ;
        RECT  618.52 349.6 618.92 350 ;
    END
  END push_block_i[511]
  PIN push_block_i[512]
    DIRECTION INPUT ;
    USE SIGNAL ;
    PORT
      LAYER Metal2 ;
        RECT  619.48 349.6 619.88 350 ;
    END
  END push_block_i[512]
  PIN push_block_i[513]
    DIRECTION INPUT ;
    USE SIGNAL ;
    PORT
      LAYER Metal2 ;
        RECT  620.44 349.6 620.84 350 ;
    END
  END push_block_i[513]
  PIN push_block_i[514]
    DIRECTION INPUT ;
    USE SIGNAL ;
    PORT
      LAYER Metal2 ;
        RECT  621.4 349.6 621.8 350 ;
    END
  END push_block_i[514]
  PIN push_block_i[515]
    DIRECTION INPUT ;
    USE SIGNAL ;
    PORT
      LAYER Metal2 ;
        RECT  622.36 349.6 622.76 350 ;
    END
  END push_block_i[515]
  PIN push_block_i[516]
    DIRECTION INPUT ;
    USE SIGNAL ;
    PORT
      LAYER Metal2 ;
        RECT  623.32 349.6 623.72 350 ;
    END
  END push_block_i[516]
  PIN push_block_i[517]
    DIRECTION INPUT ;
    USE SIGNAL ;
    PORT
      LAYER Metal2 ;
        RECT  624.28 349.6 624.68 350 ;
    END
  END push_block_i[517]
  PIN push_block_i[518]
    DIRECTION INPUT ;
    USE SIGNAL ;
    PORT
      LAYER Metal2 ;
        RECT  625.24 349.6 625.64 350 ;
    END
  END push_block_i[518]
  PIN push_block_i[519]
    DIRECTION INPUT ;
    USE SIGNAL ;
    PORT
      LAYER Metal2 ;
        RECT  626.2 349.6 626.6 350 ;
    END
  END push_block_i[519]
  PIN push_block_i[51]
    DIRECTION INPUT ;
    USE SIGNAL ;
    PORT
      LAYER Metal2 ;
        RECT  176.92 349.6 177.32 350 ;
    END
  END push_block_i[51]
  PIN push_block_i[520]
    DIRECTION INPUT ;
    USE SIGNAL ;
    PORT
      LAYER Metal2 ;
        RECT  627.16 349.6 627.56 350 ;
    END
  END push_block_i[520]
  PIN push_block_i[521]
    DIRECTION INPUT ;
    USE SIGNAL ;
    PORT
      LAYER Metal2 ;
        RECT  628.12 349.6 628.52 350 ;
    END
  END push_block_i[521]
  PIN push_block_i[522]
    DIRECTION INPUT ;
    USE SIGNAL ;
    PORT
      LAYER Metal2 ;
        RECT  629.08 349.6 629.48 350 ;
    END
  END push_block_i[522]
  PIN push_block_i[523]
    DIRECTION INPUT ;
    USE SIGNAL ;
    PORT
      LAYER Metal2 ;
        RECT  630.04 349.6 630.44 350 ;
    END
  END push_block_i[523]
  PIN push_block_i[524]
    DIRECTION INPUT ;
    USE SIGNAL ;
    PORT
      LAYER Metal2 ;
        RECT  631 349.6 631.4 350 ;
    END
  END push_block_i[524]
  PIN push_block_i[525]
    DIRECTION INPUT ;
    USE SIGNAL ;
    PORT
      LAYER Metal2 ;
        RECT  631.96 349.6 632.36 350 ;
    END
  END push_block_i[525]
  PIN push_block_i[526]
    DIRECTION INPUT ;
    USE SIGNAL ;
    PORT
      LAYER Metal2 ;
        RECT  632.92 349.6 633.32 350 ;
    END
  END push_block_i[526]
  PIN push_block_i[527]
    DIRECTION INPUT ;
    USE SIGNAL ;
    PORT
      LAYER Metal2 ;
        RECT  633.88 349.6 634.28 350 ;
    END
  END push_block_i[527]
  PIN push_block_i[528]
    DIRECTION INPUT ;
    USE SIGNAL ;
    PORT
      LAYER Metal2 ;
        RECT  634.84 349.6 635.24 350 ;
    END
  END push_block_i[528]
  PIN push_block_i[529]
    DIRECTION INPUT ;
    USE SIGNAL ;
    PORT
      LAYER Metal2 ;
        RECT  635.8 349.6 636.2 350 ;
    END
  END push_block_i[529]
  PIN push_block_i[52]
    DIRECTION INPUT ;
    USE SIGNAL ;
    PORT
      LAYER Metal2 ;
        RECT  177.88 349.6 178.28 350 ;
    END
  END push_block_i[52]
  PIN push_block_i[530]
    DIRECTION INPUT ;
    USE SIGNAL ;
    PORT
      LAYER Metal2 ;
        RECT  636.76 349.6 637.16 350 ;
    END
  END push_block_i[530]
  PIN push_block_i[531]
    DIRECTION INPUT ;
    USE SIGNAL ;
    PORT
      LAYER Metal2 ;
        RECT  637.72 349.6 638.12 350 ;
    END
  END push_block_i[531]
  PIN push_block_i[532]
    DIRECTION INPUT ;
    USE SIGNAL ;
    PORT
      LAYER Metal2 ;
        RECT  638.68 349.6 639.08 350 ;
    END
  END push_block_i[532]
  PIN push_block_i[533]
    DIRECTION INPUT ;
    USE SIGNAL ;
    PORT
      LAYER Metal2 ;
        RECT  639.64 349.6 640.04 350 ;
    END
  END push_block_i[533]
  PIN push_block_i[534]
    DIRECTION INPUT ;
    USE SIGNAL ;
    PORT
      LAYER Metal2 ;
        RECT  640.6 349.6 641 350 ;
    END
  END push_block_i[534]
  PIN push_block_i[535]
    DIRECTION INPUT ;
    USE SIGNAL ;
    PORT
      LAYER Metal2 ;
        RECT  641.56 349.6 641.96 350 ;
    END
  END push_block_i[535]
  PIN push_block_i[536]
    DIRECTION INPUT ;
    USE SIGNAL ;
    PORT
      LAYER Metal2 ;
        RECT  642.52 349.6 642.92 350 ;
    END
  END push_block_i[536]
  PIN push_block_i[537]
    DIRECTION INPUT ;
    USE SIGNAL ;
    PORT
      LAYER Metal2 ;
        RECT  643.48 349.6 643.88 350 ;
    END
  END push_block_i[537]
  PIN push_block_i[538]
    DIRECTION INPUT ;
    USE SIGNAL ;
    PORT
      LAYER Metal2 ;
        RECT  644.44 349.6 644.84 350 ;
    END
  END push_block_i[538]
  PIN push_block_i[539]
    DIRECTION INPUT ;
    USE SIGNAL ;
    PORT
      LAYER Metal2 ;
        RECT  645.4 349.6 645.8 350 ;
    END
  END push_block_i[539]
  PIN push_block_i[53]
    DIRECTION INPUT ;
    USE SIGNAL ;
    PORT
      LAYER Metal2 ;
        RECT  178.84 349.6 179.24 350 ;
    END
  END push_block_i[53]
  PIN push_block_i[540]
    DIRECTION INPUT ;
    USE SIGNAL ;
    PORT
      LAYER Metal2 ;
        RECT  646.36 349.6 646.76 350 ;
    END
  END push_block_i[540]
  PIN push_block_i[541]
    DIRECTION INPUT ;
    USE SIGNAL ;
    PORT
      LAYER Metal2 ;
        RECT  647.32 349.6 647.72 350 ;
    END
  END push_block_i[541]
  PIN push_block_i[542]
    DIRECTION INPUT ;
    USE SIGNAL ;
    PORT
      LAYER Metal2 ;
        RECT  648.28 349.6 648.68 350 ;
    END
  END push_block_i[542]
  PIN push_block_i[543]
    DIRECTION INPUT ;
    USE SIGNAL ;
    PORT
      LAYER Metal2 ;
        RECT  649.24 349.6 649.64 350 ;
    END
  END push_block_i[543]
  PIN push_block_i[544]
    DIRECTION INPUT ;
    USE SIGNAL ;
    PORT
      LAYER Metal2 ;
        RECT  650.2 349.6 650.6 350 ;
    END
  END push_block_i[544]
  PIN push_block_i[545]
    DIRECTION INPUT ;
    USE SIGNAL ;
    PORT
      LAYER Metal2 ;
        RECT  651.16 349.6 651.56 350 ;
    END
  END push_block_i[545]
  PIN push_block_i[546]
    DIRECTION INPUT ;
    USE SIGNAL ;
    PORT
      LAYER Metal2 ;
        RECT  652.12 349.6 652.52 350 ;
    END
  END push_block_i[546]
  PIN push_block_i[547]
    DIRECTION INPUT ;
    USE SIGNAL ;
    PORT
      LAYER Metal2 ;
        RECT  653.08 349.6 653.48 350 ;
    END
  END push_block_i[547]
  PIN push_block_i[548]
    DIRECTION INPUT ;
    USE SIGNAL ;
    PORT
      LAYER Metal2 ;
        RECT  654.04 349.6 654.44 350 ;
    END
  END push_block_i[548]
  PIN push_block_i[549]
    DIRECTION INPUT ;
    USE SIGNAL ;
    PORT
      LAYER Metal2 ;
        RECT  655 349.6 655.4 350 ;
    END
  END push_block_i[549]
  PIN push_block_i[54]
    DIRECTION INPUT ;
    USE SIGNAL ;
    PORT
      LAYER Metal2 ;
        RECT  179.8 349.6 180.2 350 ;
    END
  END push_block_i[54]
  PIN push_block_i[550]
    DIRECTION INPUT ;
    USE SIGNAL ;
    PORT
      LAYER Metal2 ;
        RECT  655.96 349.6 656.36 350 ;
    END
  END push_block_i[550]
  PIN push_block_i[551]
    DIRECTION INPUT ;
    USE SIGNAL ;
    PORT
      LAYER Metal2 ;
        RECT  656.92 349.6 657.32 350 ;
    END
  END push_block_i[551]
  PIN push_block_i[552]
    DIRECTION INPUT ;
    USE SIGNAL ;
    PORT
      LAYER Metal2 ;
        RECT  657.88 349.6 658.28 350 ;
    END
  END push_block_i[552]
  PIN push_block_i[553]
    DIRECTION INPUT ;
    USE SIGNAL ;
    PORT
      LAYER Metal2 ;
        RECT  658.84 349.6 659.24 350 ;
    END
  END push_block_i[553]
  PIN push_block_i[554]
    DIRECTION INPUT ;
    USE SIGNAL ;
    PORT
      LAYER Metal2 ;
        RECT  659.8 349.6 660.2 350 ;
    END
  END push_block_i[554]
  PIN push_block_i[555]
    DIRECTION INPUT ;
    USE SIGNAL ;
    PORT
      LAYER Metal2 ;
        RECT  660.76 349.6 661.16 350 ;
    END
  END push_block_i[555]
  PIN push_block_i[556]
    DIRECTION INPUT ;
    USE SIGNAL ;
    PORT
      LAYER Metal2 ;
        RECT  661.72 349.6 662.12 350 ;
    END
  END push_block_i[556]
  PIN push_block_i[557]
    DIRECTION INPUT ;
    USE SIGNAL ;
    PORT
      LAYER Metal2 ;
        RECT  662.68 349.6 663.08 350 ;
    END
  END push_block_i[557]
  PIN push_block_i[558]
    DIRECTION INPUT ;
    USE SIGNAL ;
    PORT
      LAYER Metal2 ;
        RECT  663.64 349.6 664.04 350 ;
    END
  END push_block_i[558]
  PIN push_block_i[559]
    DIRECTION INPUT ;
    USE SIGNAL ;
    PORT
      LAYER Metal2 ;
        RECT  664.6 349.6 665 350 ;
    END
  END push_block_i[559]
  PIN push_block_i[55]
    DIRECTION INPUT ;
    USE SIGNAL ;
    PORT
      LAYER Metal2 ;
        RECT  180.76 349.6 181.16 350 ;
    END
  END push_block_i[55]
  PIN push_block_i[560]
    DIRECTION INPUT ;
    USE SIGNAL ;
    PORT
      LAYER Metal2 ;
        RECT  665.56 349.6 665.96 350 ;
    END
  END push_block_i[560]
  PIN push_block_i[561]
    DIRECTION INPUT ;
    USE SIGNAL ;
    PORT
      LAYER Metal2 ;
        RECT  666.52 349.6 666.92 350 ;
    END
  END push_block_i[561]
  PIN push_block_i[562]
    DIRECTION INPUT ;
    USE SIGNAL ;
    PORT
      LAYER Metal2 ;
        RECT  667.48 349.6 667.88 350 ;
    END
  END push_block_i[562]
  PIN push_block_i[563]
    DIRECTION INPUT ;
    USE SIGNAL ;
    PORT
      LAYER Metal2 ;
        RECT  668.44 349.6 668.84 350 ;
    END
  END push_block_i[563]
  PIN push_block_i[564]
    DIRECTION INPUT ;
    USE SIGNAL ;
    PORT
      LAYER Metal2 ;
        RECT  669.4 349.6 669.8 350 ;
    END
  END push_block_i[564]
  PIN push_block_i[565]
    DIRECTION INPUT ;
    USE SIGNAL ;
    PORT
      LAYER Metal2 ;
        RECT  670.36 349.6 670.76 350 ;
    END
  END push_block_i[565]
  PIN push_block_i[566]
    DIRECTION INPUT ;
    USE SIGNAL ;
    PORT
      LAYER Metal2 ;
        RECT  671.32 349.6 671.72 350 ;
    END
  END push_block_i[566]
  PIN push_block_i[567]
    DIRECTION INPUT ;
    USE SIGNAL ;
    PORT
      LAYER Metal2 ;
        RECT  672.28 349.6 672.68 350 ;
    END
  END push_block_i[567]
  PIN push_block_i[568]
    DIRECTION INPUT ;
    USE SIGNAL ;
    PORT
      LAYER Metal2 ;
        RECT  673.24 349.6 673.64 350 ;
    END
  END push_block_i[568]
  PIN push_block_i[569]
    DIRECTION INPUT ;
    USE SIGNAL ;
    PORT
      LAYER Metal2 ;
        RECT  674.2 349.6 674.6 350 ;
    END
  END push_block_i[569]
  PIN push_block_i[56]
    DIRECTION INPUT ;
    USE SIGNAL ;
    PORT
      LAYER Metal2 ;
        RECT  181.72 349.6 182.12 350 ;
    END
  END push_block_i[56]
  PIN push_block_i[570]
    DIRECTION INPUT ;
    USE SIGNAL ;
    PORT
      LAYER Metal2 ;
        RECT  675.16 349.6 675.56 350 ;
    END
  END push_block_i[570]
  PIN push_block_i[571]
    DIRECTION INPUT ;
    USE SIGNAL ;
    PORT
      LAYER Metal2 ;
        RECT  676.12 349.6 676.52 350 ;
    END
  END push_block_i[571]
  PIN push_block_i[57]
    DIRECTION INPUT ;
    USE SIGNAL ;
    PORT
      LAYER Metal2 ;
        RECT  182.68 349.6 183.08 350 ;
    END
  END push_block_i[57]
  PIN push_block_i[58]
    DIRECTION INPUT ;
    USE SIGNAL ;
    PORT
      LAYER Metal2 ;
        RECT  183.64 349.6 184.04 350 ;
    END
  END push_block_i[58]
  PIN push_block_i[59]
    DIRECTION INPUT ;
    USE SIGNAL ;
    PORT
      LAYER Metal2 ;
        RECT  184.6 349.6 185 350 ;
    END
  END push_block_i[59]
  PIN push_block_i[5]
    DIRECTION INPUT ;
    USE SIGNAL ;
    PORT
      LAYER Metal2 ;
        RECT  132.76 349.6 133.16 350 ;
    END
  END push_block_i[5]
  PIN push_block_i[60]
    DIRECTION INPUT ;
    USE SIGNAL ;
    PORT
      LAYER Metal2 ;
        RECT  185.56 349.6 185.96 350 ;
    END
  END push_block_i[60]
  PIN push_block_i[61]
    DIRECTION INPUT ;
    USE SIGNAL ;
    PORT
      LAYER Metal2 ;
        RECT  186.52 349.6 186.92 350 ;
    END
  END push_block_i[61]
  PIN push_block_i[62]
    DIRECTION INPUT ;
    USE SIGNAL ;
    PORT
      LAYER Metal2 ;
        RECT  187.48 349.6 187.88 350 ;
    END
  END push_block_i[62]
  PIN push_block_i[63]
    DIRECTION INPUT ;
    USE SIGNAL ;
    PORT
      LAYER Metal2 ;
        RECT  188.44 349.6 188.84 350 ;
    END
  END push_block_i[63]
  PIN push_block_i[64]
    DIRECTION INPUT ;
    USE SIGNAL ;
    PORT
      LAYER Metal2 ;
        RECT  189.4 349.6 189.8 350 ;
    END
  END push_block_i[64]
  PIN push_block_i[65]
    DIRECTION INPUT ;
    USE SIGNAL ;
    PORT
      LAYER Metal2 ;
        RECT  190.36 349.6 190.76 350 ;
    END
  END push_block_i[65]
  PIN push_block_i[66]
    DIRECTION INPUT ;
    USE SIGNAL ;
    PORT
      LAYER Metal2 ;
        RECT  191.32 349.6 191.72 350 ;
    END
  END push_block_i[66]
  PIN push_block_i[67]
    DIRECTION INPUT ;
    USE SIGNAL ;
    PORT
      LAYER Metal2 ;
        RECT  192.28 349.6 192.68 350 ;
    END
  END push_block_i[67]
  PIN push_block_i[68]
    DIRECTION INPUT ;
    USE SIGNAL ;
    PORT
      LAYER Metal2 ;
        RECT  193.24 349.6 193.64 350 ;
    END
  END push_block_i[68]
  PIN push_block_i[69]
    DIRECTION INPUT ;
    USE SIGNAL ;
    PORT
      LAYER Metal2 ;
        RECT  194.2 349.6 194.6 350 ;
    END
  END push_block_i[69]
  PIN push_block_i[6]
    DIRECTION INPUT ;
    USE SIGNAL ;
    PORT
      LAYER Metal2 ;
        RECT  133.72 349.6 134.12 350 ;
    END
  END push_block_i[6]
  PIN push_block_i[70]
    DIRECTION INPUT ;
    USE SIGNAL ;
    PORT
      LAYER Metal2 ;
        RECT  195.16 349.6 195.56 350 ;
    END
  END push_block_i[70]
  PIN push_block_i[71]
    DIRECTION INPUT ;
    USE SIGNAL ;
    PORT
      LAYER Metal2 ;
        RECT  196.12 349.6 196.52 350 ;
    END
  END push_block_i[71]
  PIN push_block_i[72]
    DIRECTION INPUT ;
    USE SIGNAL ;
    PORT
      LAYER Metal2 ;
        RECT  197.08 349.6 197.48 350 ;
    END
  END push_block_i[72]
  PIN push_block_i[73]
    DIRECTION INPUT ;
    USE SIGNAL ;
    PORT
      LAYER Metal2 ;
        RECT  198.04 349.6 198.44 350 ;
    END
  END push_block_i[73]
  PIN push_block_i[74]
    DIRECTION INPUT ;
    USE SIGNAL ;
    PORT
      LAYER Metal2 ;
        RECT  199 349.6 199.4 350 ;
    END
  END push_block_i[74]
  PIN push_block_i[75]
    DIRECTION INPUT ;
    USE SIGNAL ;
    PORT
      LAYER Metal2 ;
        RECT  199.96 349.6 200.36 350 ;
    END
  END push_block_i[75]
  PIN push_block_i[76]
    DIRECTION INPUT ;
    USE SIGNAL ;
    PORT
      LAYER Metal2 ;
        RECT  200.92 349.6 201.32 350 ;
    END
  END push_block_i[76]
  PIN push_block_i[77]
    DIRECTION INPUT ;
    USE SIGNAL ;
    PORT
      LAYER Metal2 ;
        RECT  201.88 349.6 202.28 350 ;
    END
  END push_block_i[77]
  PIN push_block_i[78]
    DIRECTION INPUT ;
    USE SIGNAL ;
    PORT
      LAYER Metal2 ;
        RECT  202.84 349.6 203.24 350 ;
    END
  END push_block_i[78]
  PIN push_block_i[79]
    DIRECTION INPUT ;
    USE SIGNAL ;
    PORT
      LAYER Metal2 ;
        RECT  203.8 349.6 204.2 350 ;
    END
  END push_block_i[79]
  PIN push_block_i[7]
    DIRECTION INPUT ;
    USE SIGNAL ;
    PORT
      LAYER Metal2 ;
        RECT  134.68 349.6 135.08 350 ;
    END
  END push_block_i[7]
  PIN push_block_i[80]
    DIRECTION INPUT ;
    USE SIGNAL ;
    PORT
      LAYER Metal2 ;
        RECT  204.76 349.6 205.16 350 ;
    END
  END push_block_i[80]
  PIN push_block_i[81]
    DIRECTION INPUT ;
    USE SIGNAL ;
    PORT
      LAYER Metal2 ;
        RECT  205.72 349.6 206.12 350 ;
    END
  END push_block_i[81]
  PIN push_block_i[82]
    DIRECTION INPUT ;
    USE SIGNAL ;
    PORT
      LAYER Metal2 ;
        RECT  206.68 349.6 207.08 350 ;
    END
  END push_block_i[82]
  PIN push_block_i[83]
    DIRECTION INPUT ;
    USE SIGNAL ;
    PORT
      LAYER Metal2 ;
        RECT  207.64 349.6 208.04 350 ;
    END
  END push_block_i[83]
  PIN push_block_i[84]
    DIRECTION INPUT ;
    USE SIGNAL ;
    PORT
      LAYER Metal2 ;
        RECT  208.6 349.6 209 350 ;
    END
  END push_block_i[84]
  PIN push_block_i[85]
    DIRECTION INPUT ;
    USE SIGNAL ;
    PORT
      LAYER Metal2 ;
        RECT  209.56 349.6 209.96 350 ;
    END
  END push_block_i[85]
  PIN push_block_i[86]
    DIRECTION INPUT ;
    USE SIGNAL ;
    PORT
      LAYER Metal2 ;
        RECT  210.52 349.6 210.92 350 ;
    END
  END push_block_i[86]
  PIN push_block_i[87]
    DIRECTION INPUT ;
    USE SIGNAL ;
    PORT
      LAYER Metal2 ;
        RECT  211.48 349.6 211.88 350 ;
    END
  END push_block_i[87]
  PIN push_block_i[88]
    DIRECTION INPUT ;
    USE SIGNAL ;
    PORT
      LAYER Metal2 ;
        RECT  212.44 349.6 212.84 350 ;
    END
  END push_block_i[88]
  PIN push_block_i[89]
    DIRECTION INPUT ;
    USE SIGNAL ;
    PORT
      LAYER Metal2 ;
        RECT  213.4 349.6 213.8 350 ;
    END
  END push_block_i[89]
  PIN push_block_i[8]
    DIRECTION INPUT ;
    USE SIGNAL ;
    PORT
      LAYER Metal2 ;
        RECT  135.64 349.6 136.04 350 ;
    END
  END push_block_i[8]
  PIN push_block_i[90]
    DIRECTION INPUT ;
    USE SIGNAL ;
    PORT
      LAYER Metal2 ;
        RECT  214.36 349.6 214.76 350 ;
    END
  END push_block_i[90]
  PIN push_block_i[91]
    DIRECTION INPUT ;
    USE SIGNAL ;
    PORT
      LAYER Metal2 ;
        RECT  215.32 349.6 215.72 350 ;
    END
  END push_block_i[91]
  PIN push_block_i[92]
    DIRECTION INPUT ;
    USE SIGNAL ;
    PORT
      LAYER Metal2 ;
        RECT  216.28 349.6 216.68 350 ;
    END
  END push_block_i[92]
  PIN push_block_i[93]
    DIRECTION INPUT ;
    USE SIGNAL ;
    PORT
      LAYER Metal2 ;
        RECT  217.24 349.6 217.64 350 ;
    END
  END push_block_i[93]
  PIN push_block_i[94]
    DIRECTION INPUT ;
    USE SIGNAL ;
    PORT
      LAYER Metal2 ;
        RECT  218.2 349.6 218.6 350 ;
    END
  END push_block_i[94]
  PIN push_block_i[95]
    DIRECTION INPUT ;
    USE SIGNAL ;
    PORT
      LAYER Metal2 ;
        RECT  219.16 349.6 219.56 350 ;
    END
  END push_block_i[95]
  PIN push_block_i[96]
    DIRECTION INPUT ;
    USE SIGNAL ;
    PORT
      LAYER Metal2 ;
        RECT  220.12 349.6 220.52 350 ;
    END
  END push_block_i[96]
  PIN push_block_i[97]
    DIRECTION INPUT ;
    USE SIGNAL ;
    PORT
      LAYER Metal2 ;
        RECT  221.08 349.6 221.48 350 ;
    END
  END push_block_i[97]
  PIN push_block_i[98]
    DIRECTION INPUT ;
    USE SIGNAL ;
    PORT
      LAYER Metal2 ;
        RECT  222.04 349.6 222.44 350 ;
    END
  END push_block_i[98]
  PIN push_block_i[99]
    DIRECTION INPUT ;
    USE SIGNAL ;
    PORT
      LAYER Metal2 ;
        RECT  223 349.6 223.4 350 ;
    END
  END push_block_i[99]
  PIN push_block_i[9]
    DIRECTION INPUT ;
    USE SIGNAL ;
    PORT
      LAYER Metal2 ;
        RECT  136.6 349.6 137 350 ;
    END
  END push_block_i[9]
  PIN push_count_i[0]
    DIRECTION INPUT ;
    USE SIGNAL ;
    PORT
      LAYER Metal2 ;
        RECT  124.12 349.6 124.52 350 ;
    END
  END push_count_i[0]
  PIN push_count_i[1]
    DIRECTION INPUT ;
    USE SIGNAL ;
    PORT
      LAYER Metal2 ;
        RECT  125.08 349.6 125.48 350 ;
    END
  END push_count_i[1]
  PIN push_count_i[2]
    DIRECTION INPUT ;
    USE SIGNAL ;
    PORT
      LAYER Metal2 ;
        RECT  126.04 349.6 126.44 350 ;
    END
  END push_count_i[2]
  PIN push_count_i[3]
    DIRECTION INPUT ;
    USE SIGNAL ;
    PORT
      LAYER Metal2 ;
        RECT  127 349.6 127.4 350 ;
    END
  END push_count_i[3]
  PIN push_ready_o
    DIRECTION OUTPUT ;
    USE SIGNAL ;
    PORT
      LAYER Metal2 ;
        RECT  122.2 349.6 122.6 350 ;
    END
  END push_ready_o
  PIN push_valid_i
    DIRECTION INPUT ;
    USE SIGNAL ;
    PORT
      LAYER Metal2 ;
        RECT  123.16 349.6 123.56 350 ;
    END
  END push_valid_i
  PIN reset_i
    DIRECTION INPUT ;
    USE SIGNAL ;
    PORT
      LAYER Metal3 ;
        RECT  0 174.94 0.4 175.34 ;
    END
  END reset_i
  PIN VPWR
    DIRECTION INOUT ;
    USE POWER ;
    PORT
      LAYER TopMetal1 ;
        RECT  5.76 324.12 793.92 326.12 ;
        RECT  5.76 274.12 793.92 276.12 ;
        RECT  5.76 224.12 793.92 226.12 ;
        RECT  5.76 174.12 793.92 176.12 ;
        RECT  5.76 124.12 793.92 126.12 ;
        RECT  5.76 74.12 793.92 76.12 ;
        RECT  5.76 24.12 793.92 26.12 ;
      LAYER Metal4 ;
        RECT  765.26 14.9 766.26 332.86 ;
        RECT  715.26 14.9 716.26 332.86 ;
        RECT  665.26 14.9 666.26 332.86 ;
        RECT  615.26 14.9 616.26 332.86 ;
        RECT  565.26 14.9 566.26 332.86 ;
        RECT  515.26 14.9 516.26 332.86 ;
        RECT  465.26 14.9 466.26 332.86 ;
        RECT  415.26 14.9 416.26 332.86 ;
        RECT  365.26 14.9 366.26 332.86 ;
        RECT  315.26 14.9 316.26 332.86 ;
        RECT  265.26 14.9 266.26 332.86 ;
        RECT  215.26 14.9 216.26 332.86 ;
        RECT  165.26 14.9 166.26 332.86 ;
        RECT  115.26 14.9 116.26 332.86 ;
        RECT  65.26 14.9 66.26 332.86 ;
        RECT  15.26 14.9 16.26 332.86 ;
    END
  END VPWR
  PIN VGND
    DIRECTION INOUT ;
    USE GROUND ;
    PORT
      LAYER TopMetal1 ;
        RECT  5.76 330.12 793.92 332.12 ;
        RECT  5.76 280.12 793.92 282.12 ;
        RECT  5.76 230.12 793.92 232.12 ;
        RECT  5.76 180.12 793.92 182.12 ;
        RECT  5.76 130.12 793.92 132.12 ;
        RECT  5.76 80.12 793.92 82.12 ;
        RECT  5.76 30.12 793.92 32.12 ;
      LAYER Metal4 ;
        RECT  768.26 14.9 769.26 332.86 ;
        RECT  718.26 14.9 719.26 332.86 ;
        RECT  668.26 14.9 669.26 332.86 ;
        RECT  618.26 14.9 619.26 332.86 ;
        RECT  568.26 14.9 569.26 332.86 ;
        RECT  518.26 14.9 519.26 332.86 ;
        RECT  468.26 14.9 469.26 332.86 ;
        RECT  418.26 14.9 419.26 332.86 ;
        RECT  368.26 14.9 369.26 332.86 ;
        RECT  318.26 14.9 319.26 332.86 ;
        RECT  268.26 14.9 269.26 332.86 ;
        RECT  218.26 14.9 219.26 332.86 ;
        RECT  168.26 14.9 169.26 332.86 ;
        RECT  118.26 14.9 119.26 332.86 ;
        RECT  68.26 14.9 69.26 332.86 ;
        RECT  18.26 14.9 19.26 332.86 ;
    END
  END VGND
  OBS
    LAYER Metal1 ;
     RECT  0 0 794.5 350 ;
    LAYER Metal2 ;
     RECT  0 0 794.5 350 ;
    LAYER Metal3 ;
     RECT  0 0 794.5 350 ;
    LAYER Metal4 ;
     RECT  0 0 794.5 350 ;
    LAYER TopMetal1 ;
     RECT  0 0 794.5 350 ;
  END
END ino_decode_queue
END LIBRARY
